VERSION 5.8 ;
BUSBITCHARS "[]" ;
DIVIDERCHAR "/" ;
UNITS
    DATABASE MICRONS 1000 ;
END UNITS

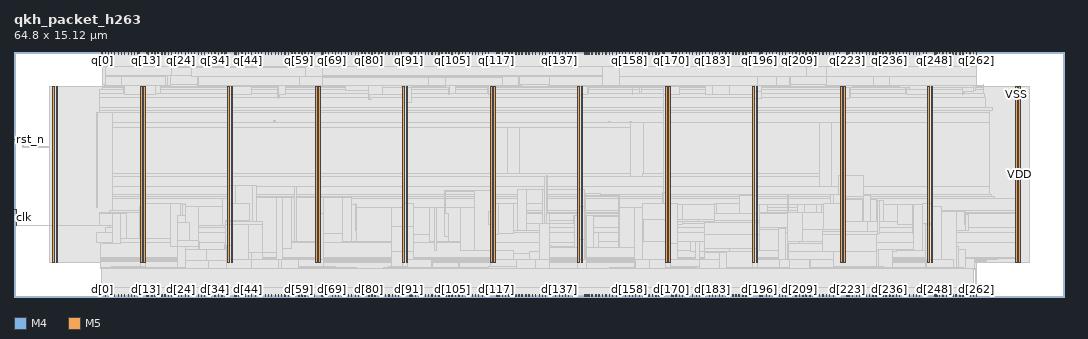
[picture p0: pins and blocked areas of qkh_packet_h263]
MACRO qkh_packet_h263
  FOREIGN qkh_packet_h263 0 0 ;
  CLASS BLOCK ;
  SIZE 64.8 BY 15.12 ;
  PIN clk
    DIRECTION INPUT ;
    USE SIGNAL ;
    PORT
      LAYER M4 ;
        RECT  0.054 5.376 0.138 5.4 ;
    END
    PORT
      LAYER M4 ;
        RECT  0.108 5.376 0.133 5.4 ;
    END
    PORT
      LAYER M4 ;
        RECT  0.133 4.416 0.179 5.4 ;
    END
  END clk
  PIN d[0]
    DIRECTION INPUT ;
    USE SIGNAL ;
    PORT
      LAYER M5 ;
        RECT  5.424 0.054 5.448 0.138 ;
    END
  END d[0]
  PIN d[100]
    DIRECTION INPUT ;
    USE SIGNAL ;
    PORT
      LAYER M5 ;
        RECT  26.016 0.054 26.04 0.138 ;
    END
  END d[100]
  PIN d[101]
    DIRECTION INPUT ;
    USE SIGNAL ;
    PORT
      LAYER M5 ;
        RECT  26.208 0.054 26.232 0.138 ;
    END
  END d[101]
  PIN d[102]
    DIRECTION INPUT ;
    USE SIGNAL ;
    PORT
      LAYER M5 ;
        RECT  26.4 0.054 26.424 0.138 ;
    END
  END d[102]
  PIN d[103]
    DIRECTION INPUT ;
    USE SIGNAL ;
    PORT
      LAYER M5 ;
        RECT  26.64 0.054 26.664 0.138 ;
    END
  END d[103]
  PIN d[104]
    DIRECTION INPUT ;
    USE SIGNAL ;
    PORT
      LAYER M5 ;
        RECT  26.832 0.054 26.856 0.138 ;
    END
  END d[104]
  PIN d[105]
    DIRECTION INPUT ;
    USE SIGNAL ;
    PORT
      LAYER M5 ;
        RECT  27.024 0.054 27.048 0.138 ;
    END
  END d[105]
  PIN d[106]
    DIRECTION INPUT ;
    USE SIGNAL ;
    PORT
      LAYER M5 ;
        RECT  27.216 0.054 27.24 0.138 ;
    END
  END d[106]
  PIN d[107]
    DIRECTION INPUT ;
    USE SIGNAL ;
    PORT
      LAYER M5 ;
        RECT  27.456 0.054 27.48 0.138 ;
    END
  END d[107]
  PIN d[108]
    DIRECTION INPUT ;
    USE SIGNAL ;
    PORT
      LAYER M5 ;
        RECT  27.648 0.054 27.672 0.138 ;
    END
  END d[108]
  PIN d[109]
    DIRECTION INPUT ;
    USE SIGNAL ;
    PORT
      LAYER M5 ;
        RECT  27.84 0.054 27.864 0.138 ;
    END
  END d[109]
  PIN d[10]
    DIRECTION INPUT ;
    USE SIGNAL ;
    PORT
      LAYER M5 ;
        RECT  7.44 0.054 7.464 0.138 ;
    END
  END d[10]
  PIN d[110]
    DIRECTION INPUT ;
    USE SIGNAL ;
    PORT
      LAYER M5 ;
        RECT  28.08 0.054 28.104 0.138 ;
    END
  END d[110]
  PIN d[111]
    DIRECTION INPUT ;
    USE SIGNAL ;
    PORT
      LAYER M5 ;
        RECT  28.272 0.054 28.296 0.138 ;
    END
  END d[111]
  PIN d[112]
    DIRECTION INPUT ;
    USE SIGNAL ;
    PORT
      LAYER M5 ;
        RECT  28.464 0.054 28.488 0.138 ;
    END
  END d[112]
  PIN d[113]
    DIRECTION INPUT ;
    USE SIGNAL ;
    PORT
      LAYER M5 ;
        RECT  28.656 0.054 28.68 0.138 ;
    END
  END d[113]
  PIN d[114]
    DIRECTION INPUT ;
    USE SIGNAL ;
    PORT
      LAYER M5 ;
        RECT  28.896 0.054 28.92 0.138 ;
    END
  END d[114]
  PIN d[115]
    DIRECTION INPUT ;
    USE SIGNAL ;
    PORT
      LAYER M5 ;
        RECT  29.088 0.054 29.112 0.138 ;
    END
  END d[115]
  PIN d[116]
    DIRECTION INPUT ;
    USE SIGNAL ;
    PORT
      LAYER M5 ;
        RECT  29.28 0.054 29.304 0.138 ;
    END
  END d[116]
  PIN d[117]
    DIRECTION INPUT ;
    USE SIGNAL ;
    PORT
      LAYER M5 ;
        RECT  29.76 0.054 29.784 0.138 ;
    END
  END d[117]
  PIN d[118]
    DIRECTION INPUT ;
    USE SIGNAL ;
    PORT
      LAYER M5 ;
        RECT  29.856 0.054 29.88 0.138 ;
    END
  END d[118]
  PIN d[119]
    DIRECTION INPUT ;
    USE SIGNAL ;
    PORT
      LAYER M5 ;
        RECT  29.952 0.054 29.976 0.138 ;
    END
  END d[119]
  PIN d[11]
    DIRECTION INPUT ;
    USE SIGNAL ;
    PORT
      LAYER M5 ;
        RECT  7.632 0.054 7.656 0.138 ;
    END
  END d[11]
  PIN d[120]
    DIRECTION INPUT ;
    USE SIGNAL ;
    PORT
      LAYER M5 ;
        RECT  30.144 0.054 30.168 0.138 ;
    END
  END d[120]
  PIN d[121]
    DIRECTION INPUT ;
    USE SIGNAL ;
    PORT
      LAYER M5 ;
        RECT  30.336 0.054 30.36 0.138 ;
    END
  END d[121]
  PIN d[122]
    DIRECTION INPUT ;
    USE SIGNAL ;
    PORT
      LAYER M5 ;
        RECT  30.528 0.054 30.552 0.138 ;
    END
  END d[122]
  PIN d[123]
    DIRECTION INPUT ;
    USE SIGNAL ;
    PORT
      LAYER M5 ;
        RECT  30.72 0.054 30.744 0.138 ;
    END
  END d[123]
  PIN d[124]
    DIRECTION INPUT ;
    USE SIGNAL ;
    PORT
      LAYER M5 ;
        RECT  30.96 0.054 30.984 0.138 ;
    END
  END d[124]
  PIN d[125]
    DIRECTION INPUT ;
    USE SIGNAL ;
    PORT
      LAYER M5 ;
        RECT  31.152 0.054 31.176 0.138 ;
    END
  END d[125]
  PIN d[126]
    DIRECTION INPUT ;
    USE SIGNAL ;
    PORT
      LAYER M5 ;
        RECT  31.344 0.054 31.368 0.138 ;
    END
  END d[126]
  PIN d[127]
    DIRECTION INPUT ;
    USE SIGNAL ;
    PORT
      LAYER M5 ;
        RECT  31.584 0.054 31.608 0.138 ;
    END
  END d[127]
  PIN d[128]
    DIRECTION INPUT ;
    USE SIGNAL ;
    PORT
      LAYER M5 ;
        RECT  31.776 0.054 31.8 0.138 ;
    END
  END d[128]
  PIN d[129]
    DIRECTION INPUT ;
    USE SIGNAL ;
    PORT
      LAYER M5 ;
        RECT  31.968 0.054 31.992 0.138 ;
    END
  END d[129]
  PIN d[12]
    DIRECTION INPUT ;
    USE SIGNAL ;
    PORT
      LAYER M5 ;
        RECT  7.728 0.054 7.752 0.138 ;
    END
  END d[12]
  PIN d[130]
    DIRECTION INPUT ;
    USE SIGNAL ;
    PORT
      LAYER M5 ;
        RECT  32.16 0.054 32.184 0.138 ;
    END
  END d[130]
  PIN d[131]
    DIRECTION INPUT ;
    USE SIGNAL ;
    PORT
      LAYER M5 ;
        RECT  32.4 0.054 32.424 0.138 ;
    END
  END d[131]
  PIN d[132]
    DIRECTION INPUT ;
    USE SIGNAL ;
    PORT
      LAYER M5 ;
        RECT  32.592 0.054 32.616 0.138 ;
    END
  END d[132]
  PIN d[133]
    DIRECTION INPUT ;
    USE SIGNAL ;
    PORT
      LAYER M5 ;
        RECT  32.784 0.054 32.808 0.138 ;
    END
  END d[133]
  PIN d[134]
    DIRECTION INPUT ;
    USE SIGNAL ;
    PORT
      LAYER M5 ;
        RECT  33.024 0.054 33.048 0.138 ;
    END
  END d[134]
  PIN d[135]
    DIRECTION INPUT ;
    USE SIGNAL ;
    PORT
      LAYER M5 ;
        RECT  33.216 0.054 33.24 0.138 ;
    END
  END d[135]
  PIN d[136]
    DIRECTION INPUT ;
    USE SIGNAL ;
    PORT
      LAYER M5 ;
        RECT  33.408 0.054 33.432 0.138 ;
    END
  END d[136]
  PIN d[137]
    DIRECTION INPUT ;
    USE SIGNAL ;
    PORT
      LAYER M5 ;
        RECT  33.648 0.054 33.672 0.138 ;
    END
  END d[137]
  PIN d[138]
    DIRECTION INPUT ;
    USE SIGNAL ;
    PORT
      LAYER M5 ;
        RECT  33.84 0.054 33.864 0.138 ;
    END
  END d[138]
  PIN d[139]
    DIRECTION INPUT ;
    USE SIGNAL ;
    PORT
      LAYER M5 ;
        RECT  34.032 0.054 34.056 0.138 ;
    END
  END d[139]
  PIN d[13]
    DIRECTION INPUT ;
    USE SIGNAL ;
    PORT
      LAYER M5 ;
        RECT  8.16 0.054 8.184 0.138 ;
    END
  END d[13]
  PIN d[140]
    DIRECTION INPUT ;
    USE SIGNAL ;
    PORT
      LAYER M5 ;
        RECT  34.224 0.054 34.248 0.138 ;
    END
  END d[140]
  PIN d[141]
    DIRECTION INPUT ;
    USE SIGNAL ;
    PORT
      LAYER M5 ;
        RECT  34.464 0.054 34.488 0.138 ;
    END
  END d[141]
  PIN d[142]
    DIRECTION INPUT ;
    USE SIGNAL ;
    PORT
      LAYER M5 ;
        RECT  34.656 0.054 34.68 0.138 ;
    END
  END d[142]
  PIN d[143]
    DIRECTION INPUT ;
    USE SIGNAL ;
    PORT
      LAYER M5 ;
        RECT  35.184 0.054 35.208 0.138 ;
    END
  END d[143]
  PIN d[144]
    DIRECTION INPUT ;
    USE SIGNAL ;
    PORT
      LAYER M5 ;
        RECT  35.28 0.054 35.304 0.138 ;
    END
  END d[144]
  PIN d[145]
    DIRECTION INPUT ;
    USE SIGNAL ;
    PORT
      LAYER M5 ;
        RECT  35.376 0.054 35.4 0.138 ;
    END
  END d[145]
  PIN d[146]
    DIRECTION INPUT ;
    USE SIGNAL ;
    PORT
      LAYER M5 ;
        RECT  35.472 0.054 35.496 0.138 ;
    END
  END d[146]
  PIN d[147]
    DIRECTION INPUT ;
    USE SIGNAL ;
    PORT
      LAYER M5 ;
        RECT  35.664 0.054 35.688 0.138 ;
    END
  END d[147]
  PIN d[148]
    DIRECTION INPUT ;
    USE SIGNAL ;
    PORT
      LAYER M5 ;
        RECT  35.904 0.054 35.928 0.138 ;
    END
  END d[148]
  PIN d[149]
    DIRECTION INPUT ;
    USE SIGNAL ;
    PORT
      LAYER M5 ;
        RECT  36.096 0.054 36.12 0.138 ;
    END
  END d[149]
  PIN d[14]
    DIRECTION INPUT ;
    USE SIGNAL ;
    PORT
      LAYER M5 ;
        RECT  8.256 0.054 8.28 0.138 ;
    END
  END d[14]
  PIN d[150]
    DIRECTION INPUT ;
    USE SIGNAL ;
    PORT
      LAYER M5 ;
        RECT  36.288 0.054 36.312 0.138 ;
    END
  END d[150]
  PIN d[151]
    DIRECTION INPUT ;
    USE SIGNAL ;
    PORT
      LAYER M5 ;
        RECT  36.528 0.054 36.552 0.138 ;
    END
  END d[151]
  PIN d[152]
    DIRECTION INPUT ;
    USE SIGNAL ;
    PORT
      LAYER M5 ;
        RECT  36.72 0.054 36.744 0.138 ;
    END
  END d[152]
  PIN d[153]
    DIRECTION INPUT ;
    USE SIGNAL ;
    PORT
      LAYER M5 ;
        RECT  36.912 0.054 36.936 0.138 ;
    END
  END d[153]
  PIN d[154]
    DIRECTION INPUT ;
    USE SIGNAL ;
    PORT
      LAYER M5 ;
        RECT  37.152 0.054 37.176 0.138 ;
    END
  END d[154]
  PIN d[155]
    DIRECTION INPUT ;
    USE SIGNAL ;
    PORT
      LAYER M5 ;
        RECT  37.344 0.054 37.368 0.138 ;
    END
  END d[155]
  PIN d[156]
    DIRECTION INPUT ;
    USE SIGNAL ;
    PORT
      LAYER M5 ;
        RECT  37.536 0.054 37.56 0.138 ;
    END
  END d[156]
  PIN d[157]
    DIRECTION INPUT ;
    USE SIGNAL ;
    PORT
      LAYER M5 ;
        RECT  37.728 0.054 37.752 0.138 ;
    END
  END d[157]
  PIN d[158]
    DIRECTION INPUT ;
    USE SIGNAL ;
    PORT
      LAYER M5 ;
        RECT  37.968 0.054 37.992 0.138 ;
    END
  END d[158]
  PIN d[159]
    DIRECTION INPUT ;
    USE SIGNAL ;
    PORT
      LAYER M5 ;
        RECT  38.16 0.054 38.184 0.138 ;
    END
  END d[159]
  PIN d[15]
    DIRECTION INPUT ;
    USE SIGNAL ;
    PORT
      LAYER M5 ;
        RECT  8.496 0.054 8.52 0.138 ;
    END
  END d[15]
  PIN d[160]
    DIRECTION INPUT ;
    USE SIGNAL ;
    PORT
      LAYER M5 ;
        RECT  38.352 0.054 38.376 0.138 ;
    END
  END d[160]
  PIN d[161]
    DIRECTION INPUT ;
    USE SIGNAL ;
    PORT
      LAYER M5 ;
        RECT  38.592 0.054 38.616 0.138 ;
    END
  END d[161]
  PIN d[162]
    DIRECTION INPUT ;
    USE SIGNAL ;
    PORT
      LAYER M5 ;
        RECT  38.784 0.054 38.808 0.138 ;
    END
  END d[162]
  PIN d[163]
    DIRECTION INPUT ;
    USE SIGNAL ;
    PORT
      LAYER M5 ;
        RECT  38.976 0.054 39 0.138 ;
    END
  END d[163]
  PIN d[164]
    DIRECTION INPUT ;
    USE SIGNAL ;
    PORT
      LAYER M5 ;
        RECT  39.168 0.054 39.192 0.138 ;
    END
  END d[164]
  PIN d[165]
    DIRECTION INPUT ;
    USE SIGNAL ;
    PORT
      LAYER M5 ;
        RECT  39.408 0.054 39.432 0.138 ;
    END
  END d[165]
  PIN d[166]
    DIRECTION INPUT ;
    USE SIGNAL ;
    PORT
      LAYER M5 ;
        RECT  39.6 0.054 39.624 0.138 ;
    END
  END d[166]
  PIN d[167]
    DIRECTION INPUT ;
    USE SIGNAL ;
    PORT
      LAYER M5 ;
        RECT  39.792 0.054 39.816 0.138 ;
    END
  END d[167]
  PIN d[168]
    DIRECTION INPUT ;
    USE SIGNAL ;
    PORT
      LAYER M5 ;
        RECT  40.032 0.054 40.056 0.138 ;
    END
  END d[168]
  PIN d[169]
    DIRECTION INPUT ;
    USE SIGNAL ;
    PORT
      LAYER M5 ;
        RECT  40.128 0.054 40.152 0.138 ;
    END
  END d[169]
  PIN d[16]
    DIRECTION INPUT ;
    USE SIGNAL ;
    PORT
      LAYER M5 ;
        RECT  8.688 0.054 8.712 0.138 ;
    END
  END d[16]
  PIN d[170]
    DIRECTION INPUT ;
    USE SIGNAL ;
    PORT
      LAYER M5 ;
        RECT  40.56 0.054 40.584 0.138 ;
    END
  END d[170]
  PIN d[171]
    DIRECTION INPUT ;
    USE SIGNAL ;
    PORT
      LAYER M5 ;
        RECT  40.656 0.054 40.68 0.138 ;
    END
  END d[171]
  PIN d[172]
    DIRECTION INPUT ;
    USE SIGNAL ;
    PORT
      LAYER M5 ;
        RECT  40.848 0.054 40.872 0.138 ;
    END
  END d[172]
  PIN d[173]
    DIRECTION INPUT ;
    USE SIGNAL ;
    PORT
      LAYER M5 ;
        RECT  41.04 0.054 41.064 0.138 ;
    END
  END d[173]
  PIN d[174]
    DIRECTION INPUT ;
    USE SIGNAL ;
    PORT
      LAYER M5 ;
        RECT  41.232 0.054 41.256 0.138 ;
    END
  END d[174]
  PIN d[175]
    DIRECTION INPUT ;
    USE SIGNAL ;
    PORT
      LAYER M5 ;
        RECT  41.472 0.054 41.496 0.138 ;
    END
  END d[175]
  PIN d[176]
    DIRECTION INPUT ;
    USE SIGNAL ;
    PORT
      LAYER M5 ;
        RECT  41.664 0.054 41.688 0.138 ;
    END
  END d[176]
  PIN d[177]
    DIRECTION INPUT ;
    USE SIGNAL ;
    PORT
      LAYER M5 ;
        RECT  41.856 0.054 41.88 0.138 ;
    END
  END d[177]
  PIN d[178]
    DIRECTION INPUT ;
    USE SIGNAL ;
    PORT
      LAYER M5 ;
        RECT  42.096 0.054 42.12 0.138 ;
    END
  END d[178]
  PIN d[179]
    DIRECTION INPUT ;
    USE SIGNAL ;
    PORT
      LAYER M5 ;
        RECT  42.288 0.054 42.312 0.138 ;
    END
  END d[179]
  PIN d[17]
    DIRECTION INPUT ;
    USE SIGNAL ;
    PORT
      LAYER M5 ;
        RECT  8.88 0.054 8.904 0.138 ;
    END
  END d[17]
  PIN d[180]
    DIRECTION INPUT ;
    USE SIGNAL ;
    PORT
      LAYER M5 ;
        RECT  42.48 0.054 42.504 0.138 ;
    END
  END d[180]
  PIN d[181]
    DIRECTION INPUT ;
    USE SIGNAL ;
    PORT
      LAYER M5 ;
        RECT  42.672 0.054 42.696 0.138 ;
    END
  END d[181]
  PIN d[182]
    DIRECTION INPUT ;
    USE SIGNAL ;
    PORT
      LAYER M5 ;
        RECT  42.912 0.054 42.936 0.138 ;
    END
  END d[182]
  PIN d[183]
    DIRECTION INPUT ;
    USE SIGNAL ;
    PORT
      LAYER M5 ;
        RECT  43.104 0.054 43.128 0.138 ;
    END
  END d[183]
  PIN d[184]
    DIRECTION INPUT ;
    USE SIGNAL ;
    PORT
      LAYER M5 ;
        RECT  43.296 0.054 43.32 0.138 ;
    END
  END d[184]
  PIN d[185]
    DIRECTION INPUT ;
    USE SIGNAL ;
    PORT
      LAYER M5 ;
        RECT  43.536 0.054 43.56 0.138 ;
    END
  END d[185]
  PIN d[186]
    DIRECTION INPUT ;
    USE SIGNAL ;
    PORT
      LAYER M5 ;
        RECT  43.728 0.054 43.752 0.138 ;
    END
  END d[186]
  PIN d[187]
    DIRECTION INPUT ;
    USE SIGNAL ;
    PORT
      LAYER M5 ;
        RECT  43.92 0.054 43.944 0.138 ;
    END
  END d[187]
  PIN d[188]
    DIRECTION INPUT ;
    USE SIGNAL ;
    PORT
      LAYER M5 ;
        RECT  44.16 0.054 44.184 0.138 ;
    END
  END d[188]
  PIN d[189]
    DIRECTION INPUT ;
    USE SIGNAL ;
    PORT
      LAYER M5 ;
        RECT  44.352 0.054 44.376 0.138 ;
    END
  END d[189]
  PIN d[18]
    DIRECTION INPUT ;
    USE SIGNAL ;
    PORT
      LAYER M5 ;
        RECT  9.12 0.054 9.144 0.138 ;
    END
  END d[18]
  PIN d[190]
    DIRECTION INPUT ;
    USE SIGNAL ;
    PORT
      LAYER M5 ;
        RECT  44.544 0.054 44.568 0.138 ;
    END
  END d[190]
  PIN d[191]
    DIRECTION INPUT ;
    USE SIGNAL ;
    PORT
      LAYER M5 ;
        RECT  44.736 0.054 44.76 0.138 ;
    END
  END d[191]
  PIN d[192]
    DIRECTION INPUT ;
    USE SIGNAL ;
    PORT
      LAYER M5 ;
        RECT  44.976 0.054 45 0.138 ;
    END
  END d[192]
  PIN d[193]
    DIRECTION INPUT ;
    USE SIGNAL ;
    PORT
      LAYER M5 ;
        RECT  45.168 0.054 45.192 0.138 ;
    END
  END d[193]
  PIN d[194]
    DIRECTION INPUT ;
    USE SIGNAL ;
    PORT
      LAYER M5 ;
        RECT  45.36 0.054 45.384 0.138 ;
    END
  END d[194]
  PIN d[195]
    DIRECTION INPUT ;
    USE SIGNAL ;
    PORT
      LAYER M5 ;
        RECT  45.504 0.054 45.528 0.138 ;
    END
  END d[195]
  PIN d[196]
    DIRECTION INPUT ;
    USE SIGNAL ;
    PORT
      LAYER M5 ;
        RECT  45.984 0.054 46.008 0.138 ;
    END
  END d[196]
  PIN d[197]
    DIRECTION INPUT ;
    USE SIGNAL ;
    PORT
      LAYER M5 ;
        RECT  46.08 0.054 46.104 0.138 ;
    END
  END d[197]
  PIN d[198]
    DIRECTION INPUT ;
    USE SIGNAL ;
    PORT
      LAYER M5 ;
        RECT  46.176 0.054 46.2 0.138 ;
    END
  END d[198]
  PIN d[199]
    DIRECTION INPUT ;
    USE SIGNAL ;
    PORT
      LAYER M5 ;
        RECT  46.416 0.054 46.44 0.138 ;
    END
  END d[199]
  PIN d[19]
    DIRECTION INPUT ;
    USE SIGNAL ;
    PORT
      LAYER M5 ;
        RECT  9.312 0.054 9.336 0.138 ;
    END
  END d[19]
  PIN d[1]
    DIRECTION INPUT ;
    USE SIGNAL ;
    PORT
      LAYER M5 ;
        RECT  5.616 0.054 5.64 0.138 ;
    END
  END d[1]
  PIN d[200]
    DIRECTION INPUT ;
    USE SIGNAL ;
    PORT
      LAYER M5 ;
        RECT  46.608 0.054 46.632 0.138 ;
    END
  END d[200]
  PIN d[201]
    DIRECTION INPUT ;
    USE SIGNAL ;
    PORT
      LAYER M5 ;
        RECT  46.8 0.054 46.824 0.138 ;
    END
  END d[201]
  PIN d[202]
    DIRECTION INPUT ;
    USE SIGNAL ;
    PORT
      LAYER M5 ;
        RECT  47.04 0.054 47.064 0.138 ;
    END
  END d[202]
  PIN d[203]
    DIRECTION INPUT ;
    USE SIGNAL ;
    PORT
      LAYER M5 ;
        RECT  47.232 0.054 47.256 0.138 ;
    END
  END d[203]
  PIN d[204]
    DIRECTION INPUT ;
    USE SIGNAL ;
    PORT
      LAYER M5 ;
        RECT  47.424 0.054 47.448 0.138 ;
    END
  END d[204]
  PIN d[205]
    DIRECTION INPUT ;
    USE SIGNAL ;
    PORT
      LAYER M5 ;
        RECT  47.616 0.054 47.64 0.138 ;
    END
  END d[205]
  PIN d[206]
    DIRECTION INPUT ;
    USE SIGNAL ;
    PORT
      LAYER M5 ;
        RECT  47.856 0.054 47.88 0.138 ;
    END
  END d[206]
  PIN d[207]
    DIRECTION INPUT ;
    USE SIGNAL ;
    PORT
      LAYER M5 ;
        RECT  48.048 0.054 48.072 0.138 ;
    END
  END d[207]
  PIN d[208]
    DIRECTION INPUT ;
    USE SIGNAL ;
    PORT
      LAYER M5 ;
        RECT  48.24 0.054 48.264 0.138 ;
    END
  END d[208]
  PIN d[209]
    DIRECTION INPUT ;
    USE SIGNAL ;
    PORT
      LAYER M5 ;
        RECT  48.48 0.054 48.504 0.138 ;
    END
  END d[209]
  PIN d[20]
    DIRECTION INPUT ;
    USE SIGNAL ;
    PORT
      LAYER M5 ;
        RECT  9.504 0.054 9.528 0.138 ;
    END
  END d[20]
  PIN d[210]
    DIRECTION INPUT ;
    USE SIGNAL ;
    PORT
      LAYER M5 ;
        RECT  48.672 0.054 48.696 0.138 ;
    END
  END d[210]
  PIN d[211]
    DIRECTION INPUT ;
    USE SIGNAL ;
    PORT
      LAYER M5 ;
        RECT  48.864 0.054 48.888 0.138 ;
    END
  END d[211]
  PIN d[212]
    DIRECTION INPUT ;
    USE SIGNAL ;
    PORT
      LAYER M5 ;
        RECT  49.104 0.054 49.128 0.138 ;
    END
  END d[212]
  PIN d[213]
    DIRECTION INPUT ;
    USE SIGNAL ;
    PORT
      LAYER M5 ;
        RECT  49.296 0.054 49.32 0.138 ;
    END
  END d[213]
  PIN d[214]
    DIRECTION INPUT ;
    USE SIGNAL ;
    PORT
      LAYER M5 ;
        RECT  49.488 0.054 49.512 0.138 ;
    END
  END d[214]
  PIN d[215]
    DIRECTION INPUT ;
    USE SIGNAL ;
    PORT
      LAYER M5 ;
        RECT  49.68 0.054 49.704 0.138 ;
    END
  END d[215]
  PIN d[216]
    DIRECTION INPUT ;
    USE SIGNAL ;
    PORT
      LAYER M5 ;
        RECT  49.92 0.054 49.944 0.138 ;
    END
  END d[216]
  PIN d[217]
    DIRECTION INPUT ;
    USE SIGNAL ;
    PORT
      LAYER M5 ;
        RECT  50.112 0.054 50.136 0.138 ;
    END
  END d[217]
  PIN d[218]
    DIRECTION INPUT ;
    USE SIGNAL ;
    PORT
      LAYER M5 ;
        RECT  50.304 0.054 50.328 0.138 ;
    END
  END d[218]
  PIN d[219]
    DIRECTION INPUT ;
    USE SIGNAL ;
    PORT
      LAYER M5 ;
        RECT  50.544 0.054 50.568 0.138 ;
    END
  END d[219]
  PIN d[21]
    DIRECTION INPUT ;
    USE SIGNAL ;
    PORT
      LAYER M5 ;
        RECT  9.696 0.054 9.72 0.138 ;
    END
  END d[21]
  PIN d[220]
    DIRECTION INPUT ;
    USE SIGNAL ;
    PORT
      LAYER M5 ;
        RECT  50.736 0.054 50.76 0.138 ;
    END
  END d[220]
  PIN d[221]
    DIRECTION INPUT ;
    USE SIGNAL ;
    PORT
      LAYER M5 ;
        RECT  50.928 0.054 50.952 0.138 ;
    END
  END d[221]
  PIN d[222]
    DIRECTION INPUT ;
    USE SIGNAL ;
    PORT
      LAYER M5 ;
        RECT  51.36 0.054 51.384 0.138 ;
    END
  END d[222]
  PIN d[223]
    DIRECTION INPUT ;
    USE SIGNAL ;
    PORT
      LAYER M5 ;
        RECT  51.456 0.054 51.48 0.138 ;
    END
  END d[223]
  PIN d[224]
    DIRECTION INPUT ;
    USE SIGNAL ;
    PORT
      LAYER M5 ;
        RECT  51.552 0.054 51.576 0.138 ;
    END
  END d[224]
  PIN d[225]
    DIRECTION INPUT ;
    USE SIGNAL ;
    PORT
      LAYER M5 ;
        RECT  51.744 0.054 51.768 0.138 ;
    END
  END d[225]
  PIN d[226]
    DIRECTION INPUT ;
    USE SIGNAL ;
    PORT
      LAYER M5 ;
        RECT  51.984 0.054 52.008 0.138 ;
    END
  END d[226]
  PIN d[227]
    DIRECTION INPUT ;
    USE SIGNAL ;
    PORT
      LAYER M5 ;
        RECT  52.176 0.054 52.2 0.138 ;
    END
  END d[227]
  PIN d[228]
    DIRECTION INPUT ;
    USE SIGNAL ;
    PORT
      LAYER M5 ;
        RECT  52.368 0.054 52.392 0.138 ;
    END
  END d[228]
  PIN d[229]
    DIRECTION INPUT ;
    USE SIGNAL ;
    PORT
      LAYER M5 ;
        RECT  52.608 0.054 52.632 0.138 ;
    END
  END d[229]
  PIN d[22]
    DIRECTION INPUT ;
    USE SIGNAL ;
    PORT
      LAYER M5 ;
        RECT  9.936 0.054 9.96 0.138 ;
    END
  END d[22]
  PIN d[230]
    DIRECTION INPUT ;
    USE SIGNAL ;
    PORT
      LAYER M5 ;
        RECT  52.8 0.054 52.824 0.138 ;
    END
  END d[230]
  PIN d[231]
    DIRECTION INPUT ;
    USE SIGNAL ;
    PORT
      LAYER M5 ;
        RECT  52.992 0.054 53.016 0.138 ;
    END
  END d[231]
  PIN d[232]
    DIRECTION INPUT ;
    USE SIGNAL ;
    PORT
      LAYER M5 ;
        RECT  53.184 0.054 53.208 0.138 ;
    END
  END d[232]
  PIN d[233]
    DIRECTION INPUT ;
    USE SIGNAL ;
    PORT
      LAYER M5 ;
        RECT  53.424 0.054 53.448 0.138 ;
    END
  END d[233]
  PIN d[234]
    DIRECTION INPUT ;
    USE SIGNAL ;
    PORT
      LAYER M5 ;
        RECT  53.616 0.054 53.64 0.138 ;
    END
  END d[234]
  PIN d[235]
    DIRECTION INPUT ;
    USE SIGNAL ;
    PORT
      LAYER M5 ;
        RECT  53.808 0.054 53.832 0.138 ;
    END
  END d[235]
  PIN d[236]
    DIRECTION INPUT ;
    USE SIGNAL ;
    PORT
      LAYER M5 ;
        RECT  54.048 0.054 54.072 0.138 ;
    END
  END d[236]
  PIN d[237]
    DIRECTION INPUT ;
    USE SIGNAL ;
    PORT
      LAYER M5 ;
        RECT  54.24 0.054 54.264 0.138 ;
    END
  END d[237]
  PIN d[238]
    DIRECTION INPUT ;
    USE SIGNAL ;
    PORT
      LAYER M5 ;
        RECT  54.432 0.054 54.456 0.138 ;
    END
  END d[238]
  PIN d[239]
    DIRECTION INPUT ;
    USE SIGNAL ;
    PORT
      LAYER M5 ;
        RECT  54.624 0.054 54.648 0.138 ;
    END
  END d[239]
  PIN d[23]
    DIRECTION INPUT ;
    USE SIGNAL ;
    PORT
      LAYER M5 ;
        RECT  10.128 0.054 10.152 0.138 ;
    END
  END d[23]
  PIN d[240]
    DIRECTION INPUT ;
    USE SIGNAL ;
    PORT
      LAYER M5 ;
        RECT  54.864 0.054 54.888 0.138 ;
    END
  END d[240]
  PIN d[241]
    DIRECTION INPUT ;
    USE SIGNAL ;
    PORT
      LAYER M5 ;
        RECT  55.056 0.054 55.08 0.138 ;
    END
  END d[241]
  PIN d[242]
    DIRECTION INPUT ;
    USE SIGNAL ;
    PORT
      LAYER M5 ;
        RECT  55.248 0.054 55.272 0.138 ;
    END
  END d[242]
  PIN d[243]
    DIRECTION INPUT ;
    USE SIGNAL ;
    PORT
      LAYER M5 ;
        RECT  55.488 0.054 55.512 0.138 ;
    END
  END d[243]
  PIN d[244]
    DIRECTION INPUT ;
    USE SIGNAL ;
    PORT
      LAYER M5 ;
        RECT  55.68 0.054 55.704 0.138 ;
    END
  END d[244]
  PIN d[245]
    DIRECTION INPUT ;
    USE SIGNAL ;
    PORT
      LAYER M5 ;
        RECT  55.872 0.054 55.896 0.138 ;
    END
  END d[245]
  PIN d[246]
    DIRECTION INPUT ;
    USE SIGNAL ;
    PORT
      LAYER M5 ;
        RECT  56.112 0.054 56.136 0.138 ;
    END
  END d[246]
  PIN d[247]
    DIRECTION INPUT ;
    USE SIGNAL ;
    PORT
      LAYER M5 ;
        RECT  56.304 0.054 56.328 0.138 ;
    END
  END d[247]
  PIN d[248]
    DIRECTION INPUT ;
    USE SIGNAL ;
    PORT
      LAYER M5 ;
        RECT  56.784 0.054 56.808 0.138 ;
    END
  END d[248]
  PIN d[249]
    DIRECTION INPUT ;
    USE SIGNAL ;
    PORT
      LAYER M5 ;
        RECT  56.88 0.054 56.904 0.138 ;
    END
  END d[249]
  PIN d[24]
    DIRECTION INPUT ;
    USE SIGNAL ;
    PORT
      LAYER M5 ;
        RECT  10.32 0.054 10.344 0.138 ;
    END
  END d[24]
  PIN d[250]
    DIRECTION INPUT ;
    USE SIGNAL ;
    PORT
      LAYER M5 ;
        RECT  56.976 0.054 57 0.138 ;
    END
  END d[250]
  PIN d[251]
    DIRECTION INPUT ;
    USE SIGNAL ;
    PORT
      LAYER M5 ;
        RECT  57.12 0.054 57.144 0.138 ;
    END
  END d[251]
  PIN d[252]
    DIRECTION INPUT ;
    USE SIGNAL ;
    PORT
      LAYER M5 ;
        RECT  57.312 0.054 57.336 0.138 ;
    END
  END d[252]
  PIN d[253]
    DIRECTION INPUT ;
    USE SIGNAL ;
    PORT
      LAYER M5 ;
        RECT  57.552 0.054 57.576 0.138 ;
    END
  END d[253]
  PIN d[254]
    DIRECTION INPUT ;
    USE SIGNAL ;
    PORT
      LAYER M5 ;
        RECT  57.744 0.054 57.768 0.138 ;
    END
  END d[254]
  PIN d[255]
    DIRECTION INPUT ;
    USE SIGNAL ;
    PORT
      LAYER M5 ;
        RECT  57.936 0.054 57.96 0.138 ;
    END
  END d[255]
  PIN d[256]
    DIRECTION INPUT ;
    USE SIGNAL ;
    PORT
      LAYER M5 ;
        RECT  58.128 0.054 58.152 0.138 ;
    END
  END d[256]
  PIN d[257]
    DIRECTION INPUT ;
    USE SIGNAL ;
    PORT
      LAYER M5 ;
        RECT  58.368 0.054 58.392 0.138 ;
    END
  END d[257]
  PIN d[258]
    DIRECTION INPUT ;
    USE SIGNAL ;
    PORT
      LAYER M5 ;
        RECT  58.56 0.054 58.584 0.138 ;
    END
  END d[258]
  PIN d[259]
    DIRECTION INPUT ;
    USE SIGNAL ;
    PORT
      LAYER M5 ;
        RECT  58.752 0.054 58.776 0.138 ;
    END
  END d[259]
  PIN d[25]
    DIRECTION INPUT ;
    USE SIGNAL ;
    PORT
      LAYER M5 ;
        RECT  10.56 0.054 10.584 0.138 ;
    END
  END d[25]
  PIN d[260]
    DIRECTION INPUT ;
    USE SIGNAL ;
    PORT
      LAYER M5 ;
        RECT  58.992 0.054 59.016 0.138 ;
    END
  END d[260]
  PIN d[261]
    DIRECTION INPUT ;
    USE SIGNAL ;
    PORT
      LAYER M5 ;
        RECT  59.184 0.054 59.208 0.138 ;
    END
  END d[261]
  PIN d[262]
    DIRECTION INPUT ;
    USE SIGNAL ;
    PORT
      LAYER M5 ;
        RECT  59.376 0.054 59.4 0.138 ;
    END
  END d[262]
  PIN d[26]
    DIRECTION INPUT ;
    USE SIGNAL ;
    PORT
      LAYER M5 ;
        RECT  10.752 0.054 10.776 0.138 ;
    END
  END d[26]
  PIN d[27]
    DIRECTION INPUT ;
    USE SIGNAL ;
    PORT
      LAYER M5 ;
        RECT  10.944 0.054 10.968 0.138 ;
    END
  END d[27]
  PIN d[28]
    DIRECTION INPUT ;
    USE SIGNAL ;
    PORT
      LAYER M5 ;
        RECT  11.136 0.054 11.16 0.138 ;
    END
  END d[28]
  PIN d[29]
    DIRECTION INPUT ;
    USE SIGNAL ;
    PORT
      LAYER M5 ;
        RECT  11.376 0.054 11.4 0.138 ;
    END
  END d[29]
  PIN d[2]
    DIRECTION INPUT ;
    USE SIGNAL ;
    PORT
      LAYER M5 ;
        RECT  5.808 0.054 5.832 0.138 ;
    END
  END d[2]
  PIN d[30]
    DIRECTION INPUT ;
    USE SIGNAL ;
    PORT
      LAYER M5 ;
        RECT  11.568 0.054 11.592 0.138 ;
    END
  END d[30]
  PIN d[31]
    DIRECTION INPUT ;
    USE SIGNAL ;
    PORT
      LAYER M5 ;
        RECT  11.76 0.054 11.784 0.138 ;
    END
  END d[31]
  PIN d[32]
    DIRECTION INPUT ;
    USE SIGNAL ;
    PORT
      LAYER M5 ;
        RECT  12 0.054 12.024 0.138 ;
    END
  END d[32]
  PIN d[33]
    DIRECTION INPUT ;
    USE SIGNAL ;
    PORT
      LAYER M5 ;
        RECT  12.192 0.054 12.216 0.138 ;
    END
  END d[33]
  PIN d[34]
    DIRECTION INPUT ;
    USE SIGNAL ;
    PORT
      LAYER M5 ;
        RECT  12.384 0.054 12.408 0.138 ;
    END
  END d[34]
  PIN d[35]
    DIRECTION INPUT ;
    USE SIGNAL ;
    PORT
      LAYER M5 ;
        RECT  12.624 0.054 12.648 0.138 ;
    END
  END d[35]
  PIN d[36]
    DIRECTION INPUT ;
    USE SIGNAL ;
    PORT
      LAYER M5 ;
        RECT  12.816 0.054 12.84 0.138 ;
    END
  END d[36]
  PIN d[37]
    DIRECTION INPUT ;
    USE SIGNAL ;
    PORT
      LAYER M5 ;
        RECT  13.008 0.054 13.032 0.138 ;
    END
  END d[37]
  PIN d[38]
    DIRECTION INPUT ;
    USE SIGNAL ;
    PORT
      LAYER M5 ;
        RECT  13.104 0.054 13.128 0.138 ;
    END
  END d[38]
  PIN d[39]
    DIRECTION INPUT ;
    USE SIGNAL ;
    PORT
      LAYER M5 ;
        RECT  13.584 0.054 13.608 0.138 ;
    END
  END d[39]
  PIN d[3]
    DIRECTION INPUT ;
    USE SIGNAL ;
    PORT
      LAYER M5 ;
        RECT  6 0.054 6.024 0.138 ;
    END
  END d[3]
  PIN d[40]
    DIRECTION INPUT ;
    USE SIGNAL ;
    PORT
      LAYER M5 ;
        RECT  13.68 0.054 13.704 0.138 ;
    END
  END d[40]
  PIN d[41]
    DIRECTION INPUT ;
    USE SIGNAL ;
    PORT
      LAYER M5 ;
        RECT  13.824 0.054 13.848 0.138 ;
    END
  END d[41]
  PIN d[42]
    DIRECTION INPUT ;
    USE SIGNAL ;
    PORT
      LAYER M5 ;
        RECT  14.064 0.054 14.088 0.138 ;
    END
  END d[42]
  PIN d[43]
    DIRECTION INPUT ;
    USE SIGNAL ;
    PORT
      LAYER M5 ;
        RECT  14.256 0.054 14.28 0.138 ;
    END
  END d[43]
  PIN d[44]
    DIRECTION INPUT ;
    USE SIGNAL ;
    PORT
      LAYER M5 ;
        RECT  14.448 0.054 14.472 0.138 ;
    END
  END d[44]
  PIN d[45]
    DIRECTION INPUT ;
    USE SIGNAL ;
    PORT
      LAYER M5 ;
        RECT  14.64 0.054 14.664 0.138 ;
    END
  END d[45]
  PIN d[46]
    DIRECTION INPUT ;
    USE SIGNAL ;
    PORT
      LAYER M5 ;
        RECT  14.88 0.054 14.904 0.138 ;
    END
  END d[46]
  PIN d[47]
    DIRECTION INPUT ;
    USE SIGNAL ;
    PORT
      LAYER M5 ;
        RECT  15.072 0.054 15.096 0.138 ;
    END
  END d[47]
  PIN d[48]
    DIRECTION INPUT ;
    USE SIGNAL ;
    PORT
      LAYER M5 ;
        RECT  15.264 0.054 15.288 0.138 ;
    END
  END d[48]
  PIN d[49]
    DIRECTION INPUT ;
    USE SIGNAL ;
    PORT
      LAYER M5 ;
        RECT  15.504 0.054 15.528 0.138 ;
    END
  END d[49]
  PIN d[4]
    DIRECTION INPUT ;
    USE SIGNAL ;
    PORT
      LAYER M5 ;
        RECT  6.192 0.054 6.216 0.138 ;
    END
  END d[4]
  PIN d[50]
    DIRECTION INPUT ;
    USE SIGNAL ;
    PORT
      LAYER M5 ;
        RECT  15.696 0.054 15.72 0.138 ;
    END
  END d[50]
  PIN d[51]
    DIRECTION INPUT ;
    USE SIGNAL ;
    PORT
      LAYER M5 ;
        RECT  15.888 0.054 15.912 0.138 ;
    END
  END d[51]
  PIN d[52]
    DIRECTION INPUT ;
    USE SIGNAL ;
    PORT
      LAYER M5 ;
        RECT  16.128 0.054 16.152 0.138 ;
    END
  END d[52]
  PIN d[53]
    DIRECTION INPUT ;
    USE SIGNAL ;
    PORT
      LAYER M5 ;
        RECT  16.32 0.054 16.344 0.138 ;
    END
  END d[53]
  PIN d[54]
    DIRECTION INPUT ;
    USE SIGNAL ;
    PORT
      LAYER M5 ;
        RECT  16.512 0.054 16.536 0.138 ;
    END
  END d[54]
  PIN d[55]
    DIRECTION INPUT ;
    USE SIGNAL ;
    PORT
      LAYER M5 ;
        RECT  16.704 0.054 16.728 0.138 ;
    END
  END d[55]
  PIN d[56]
    DIRECTION INPUT ;
    USE SIGNAL ;
    PORT
      LAYER M5 ;
        RECT  16.944 0.054 16.968 0.138 ;
    END
  END d[56]
  PIN d[57]
    DIRECTION INPUT ;
    USE SIGNAL ;
    PORT
      LAYER M5 ;
        RECT  17.136 0.054 17.16 0.138 ;
    END
  END d[57]
  PIN d[58]
    DIRECTION INPUT ;
    USE SIGNAL ;
    PORT
      LAYER M5 ;
        RECT  17.328 0.054 17.352 0.138 ;
    END
  END d[58]
  PIN d[59]
    DIRECTION INPUT ;
    USE SIGNAL ;
    PORT
      LAYER M5 ;
        RECT  17.568 0.054 17.592 0.138 ;
    END
  END d[59]
  PIN d[5]
    DIRECTION INPUT ;
    USE SIGNAL ;
    PORT
      LAYER M5 ;
        RECT  6.432 0.054 6.456 0.138 ;
    END
  END d[5]
  PIN d[60]
    DIRECTION INPUT ;
    USE SIGNAL ;
    PORT
      LAYER M5 ;
        RECT  17.76 0.054 17.784 0.138 ;
    END
  END d[60]
  PIN d[61]
    DIRECTION INPUT ;
    USE SIGNAL ;
    PORT
      LAYER M5 ;
        RECT  17.952 0.054 17.976 0.138 ;
    END
  END d[61]
  PIN d[62]
    DIRECTION INPUT ;
    USE SIGNAL ;
    PORT
      LAYER M5 ;
        RECT  18.144 0.054 18.168 0.138 ;
    END
  END d[62]
  PIN d[63]
    DIRECTION INPUT ;
    USE SIGNAL ;
    PORT
      LAYER M5 ;
        RECT  18.384 0.054 18.408 0.138 ;
    END
  END d[63]
  PIN d[64]
    DIRECTION INPUT ;
    USE SIGNAL ;
    PORT
      LAYER M5 ;
        RECT  18.528 0.054 18.552 0.138 ;
    END
  END d[64]
  PIN d[65]
    DIRECTION INPUT ;
    USE SIGNAL ;
    PORT
      LAYER M5 ;
        RECT  18.96 0.054 18.984 0.138 ;
    END
  END d[65]
  PIN d[66]
    DIRECTION INPUT ;
    USE SIGNAL ;
    PORT
      LAYER M5 ;
        RECT  19.056 0.054 19.08 0.138 ;
    END
  END d[66]
  PIN d[67]
    DIRECTION INPUT ;
    USE SIGNAL ;
    PORT
      LAYER M5 ;
        RECT  19.2 0.054 19.224 0.138 ;
    END
  END d[67]
  PIN d[68]
    DIRECTION INPUT ;
    USE SIGNAL ;
    PORT
      LAYER M5 ;
        RECT  19.392 0.054 19.416 0.138 ;
    END
  END d[68]
  PIN d[69]
    DIRECTION INPUT ;
    USE SIGNAL ;
    PORT
      LAYER M5 ;
        RECT  19.632 0.054 19.656 0.138 ;
    END
  END d[69]
  PIN d[6]
    DIRECTION INPUT ;
    USE SIGNAL ;
    PORT
      LAYER M5 ;
        RECT  6.624 0.054 6.648 0.138 ;
    END
  END d[6]
  PIN d[70]
    DIRECTION INPUT ;
    USE SIGNAL ;
    PORT
      LAYER M5 ;
        RECT  19.824 0.054 19.848 0.138 ;
    END
  END d[70]
  PIN d[71]
    DIRECTION INPUT ;
    USE SIGNAL ;
    PORT
      LAYER M5 ;
        RECT  20.016 0.054 20.04 0.138 ;
    END
  END d[71]
  PIN d[72]
    DIRECTION INPUT ;
    USE SIGNAL ;
    PORT
      LAYER M5 ;
        RECT  20.208 0.054 20.232 0.138 ;
    END
  END d[72]
  PIN d[73]
    DIRECTION INPUT ;
    USE SIGNAL ;
    PORT
      LAYER M5 ;
        RECT  20.448 0.054 20.472 0.138 ;
    END
  END d[73]
  PIN d[74]
    DIRECTION INPUT ;
    USE SIGNAL ;
    PORT
      LAYER M5 ;
        RECT  20.64 0.054 20.664 0.138 ;
    END
  END d[74]
  PIN d[75]
    DIRECTION INPUT ;
    USE SIGNAL ;
    PORT
      LAYER M5 ;
        RECT  20.832 0.054 20.856 0.138 ;
    END
  END d[75]
  PIN d[76]
    DIRECTION INPUT ;
    USE SIGNAL ;
    PORT
      LAYER M5 ;
        RECT  21.072 0.054 21.096 0.138 ;
    END
  END d[76]
  PIN d[77]
    DIRECTION INPUT ;
    USE SIGNAL ;
    PORT
      LAYER M5 ;
        RECT  21.264 0.054 21.288 0.138 ;
    END
  END d[77]
  PIN d[78]
    DIRECTION INPUT ;
    USE SIGNAL ;
    PORT
      LAYER M5 ;
        RECT  21.456 0.054 21.48 0.138 ;
    END
  END d[78]
  PIN d[79]
    DIRECTION INPUT ;
    USE SIGNAL ;
    PORT
      LAYER M5 ;
        RECT  21.648 0.054 21.672 0.138 ;
    END
  END d[79]
  PIN d[7]
    DIRECTION INPUT ;
    USE SIGNAL ;
    PORT
      LAYER M5 ;
        RECT  6.816 0.054 6.84 0.138 ;
    END
  END d[7]
  PIN d[80]
    DIRECTION INPUT ;
    USE SIGNAL ;
    PORT
      LAYER M5 ;
        RECT  21.888 0.054 21.912 0.138 ;
    END
  END d[80]
  PIN d[81]
    DIRECTION INPUT ;
    USE SIGNAL ;
    PORT
      LAYER M5 ;
        RECT  22.08 0.054 22.104 0.138 ;
    END
  END d[81]
  PIN d[82]
    DIRECTION INPUT ;
    USE SIGNAL ;
    PORT
      LAYER M5 ;
        RECT  22.272 0.054 22.296 0.138 ;
    END
  END d[82]
  PIN d[83]
    DIRECTION INPUT ;
    USE SIGNAL ;
    PORT
      LAYER M5 ;
        RECT  22.512 0.054 22.536 0.138 ;
    END
  END d[83]
  PIN d[84]
    DIRECTION INPUT ;
    USE SIGNAL ;
    PORT
      LAYER M5 ;
        RECT  22.704 0.054 22.728 0.138 ;
    END
  END d[84]
  PIN d[85]
    DIRECTION INPUT ;
    USE SIGNAL ;
    PORT
      LAYER M5 ;
        RECT  22.896 0.054 22.92 0.138 ;
    END
  END d[85]
  PIN d[86]
    DIRECTION INPUT ;
    USE SIGNAL ;
    PORT
      LAYER M5 ;
        RECT  23.136 0.054 23.16 0.138 ;
    END
  END d[86]
  PIN d[87]
    DIRECTION INPUT ;
    USE SIGNAL ;
    PORT
      LAYER M5 ;
        RECT  23.328 0.054 23.352 0.138 ;
    END
  END d[87]
  PIN d[88]
    DIRECTION INPUT ;
    USE SIGNAL ;
    PORT
      LAYER M5 ;
        RECT  23.52 0.054 23.544 0.138 ;
    END
  END d[88]
  PIN d[89]
    DIRECTION INPUT ;
    USE SIGNAL ;
    PORT
      LAYER M5 ;
        RECT  23.712 0.054 23.736 0.138 ;
    END
  END d[89]
  PIN d[8]
    DIRECTION INPUT ;
    USE SIGNAL ;
    PORT
      LAYER M5 ;
        RECT  7.056 0.054 7.08 0.138 ;
    END
  END d[8]
  PIN d[90]
    DIRECTION INPUT ;
    USE SIGNAL ;
    PORT
      LAYER M5 ;
        RECT  23.904 0.054 23.928 0.138 ;
    END
  END d[90]
  PIN d[91]
    DIRECTION INPUT ;
    USE SIGNAL ;
    PORT
      LAYER M5 ;
        RECT  24.384 0.054 24.408 0.138 ;
    END
  END d[91]
  PIN d[92]
    DIRECTION INPUT ;
    USE SIGNAL ;
    PORT
      LAYER M5 ;
        RECT  24.48 0.054 24.504 0.138 ;
    END
  END d[92]
  PIN d[93]
    DIRECTION INPUT ;
    USE SIGNAL ;
    PORT
      LAYER M5 ;
        RECT  24.576 0.054 24.6 0.138 ;
    END
  END d[93]
  PIN d[94]
    DIRECTION INPUT ;
    USE SIGNAL ;
    PORT
      LAYER M5 ;
        RECT  24.768 0.054 24.792 0.138 ;
    END
  END d[94]
  PIN d[95]
    DIRECTION INPUT ;
    USE SIGNAL ;
    PORT
      LAYER M5 ;
        RECT  24.96 0.054 24.984 0.138 ;
    END
  END d[95]
  PIN d[96]
    DIRECTION INPUT ;
    USE SIGNAL ;
    PORT
      LAYER M5 ;
        RECT  25.152 0.054 25.176 0.138 ;
    END
  END d[96]
  PIN d[97]
    DIRECTION INPUT ;
    USE SIGNAL ;
    PORT
      LAYER M5 ;
        RECT  25.392 0.054 25.416 0.138 ;
    END
  END d[97]
  PIN d[98]
    DIRECTION INPUT ;
    USE SIGNAL ;
    PORT
      LAYER M5 ;
        RECT  25.584 0.054 25.608 0.138 ;
    END
  END d[98]
  PIN d[99]
    DIRECTION INPUT ;
    USE SIGNAL ;
    PORT
      LAYER M5 ;
        RECT  25.776 0.054 25.8 0.138 ;
    END
  END d[99]
  PIN d[9]
    DIRECTION INPUT ;
    USE SIGNAL ;
    PORT
      LAYER M5 ;
        RECT  7.248 0.054 7.272 0.138 ;
    END
  END d[9]
  PIN q[0]
    DIRECTION OUTPUT ;
    USE SIGNAL ;
    PORT
      LAYER M5 ;
        RECT  5.424 14.982 5.448 15.066 ;
    END
  END q[0]
  PIN q[100]
    DIRECTION OUTPUT ;
    USE SIGNAL ;
    PORT
      LAYER M5 ;
        RECT  26.016 14.982 26.04 15.066 ;
    END
  END q[100]
  PIN q[101]
    DIRECTION OUTPUT ;
    USE SIGNAL ;
    PORT
      LAYER M5 ;
        RECT  26.208 14.982 26.232 15.066 ;
    END
  END q[101]
  PIN q[102]
    DIRECTION OUTPUT ;
    USE SIGNAL ;
    PORT
      LAYER M5 ;
        RECT  26.4 14.982 26.424 15.066 ;
    END
  END q[102]
  PIN q[103]
    DIRECTION OUTPUT ;
    USE SIGNAL ;
    PORT
      LAYER M5 ;
        RECT  26.64 14.982 26.664 15.066 ;
    END
  END q[103]
  PIN q[104]
    DIRECTION OUTPUT ;
    USE SIGNAL ;
    PORT
      LAYER M5 ;
        RECT  26.832 14.982 26.856 15.066 ;
    END
  END q[104]
  PIN q[105]
    DIRECTION OUTPUT ;
    USE SIGNAL ;
    PORT
      LAYER M5 ;
        RECT  27.024 14.982 27.048 15.066 ;
    END
  END q[105]
  PIN q[106]
    DIRECTION OUTPUT ;
    USE SIGNAL ;
    PORT
      LAYER M5 ;
        RECT  27.216 14.982 27.24 15.066 ;
    END
  END q[106]
  PIN q[107]
    DIRECTION OUTPUT ;
    USE SIGNAL ;
    PORT
      LAYER M5 ;
        RECT  27.456 14.982 27.48 15.066 ;
    END
  END q[107]
  PIN q[108]
    DIRECTION OUTPUT ;
    USE SIGNAL ;
    PORT
      LAYER M5 ;
        RECT  27.648 14.982 27.672 15.066 ;
    END
  END q[108]
  PIN q[109]
    DIRECTION OUTPUT ;
    USE SIGNAL ;
    PORT
      LAYER M5 ;
        RECT  27.84 14.982 27.864 15.066 ;
    END
  END q[109]
  PIN q[10]
    DIRECTION OUTPUT ;
    USE SIGNAL ;
    PORT
      LAYER M5 ;
        RECT  7.44 14.982 7.464 15.066 ;
    END
  END q[10]
  PIN q[110]
    DIRECTION OUTPUT ;
    USE SIGNAL ;
    PORT
      LAYER M5 ;
        RECT  28.08 14.982 28.104 15.066 ;
    END
  END q[110]
  PIN q[111]
    DIRECTION OUTPUT ;
    USE SIGNAL ;
    PORT
      LAYER M5 ;
        RECT  28.272 14.982 28.296 15.066 ;
    END
  END q[111]
  PIN q[112]
    DIRECTION OUTPUT ;
    USE SIGNAL ;
    PORT
      LAYER M5 ;
        RECT  28.464 14.982 28.488 15.066 ;
    END
  END q[112]
  PIN q[113]
    DIRECTION OUTPUT ;
    USE SIGNAL ;
    PORT
      LAYER M5 ;
        RECT  28.656 14.982 28.68 15.066 ;
    END
  END q[113]
  PIN q[114]
    DIRECTION OUTPUT ;
    USE SIGNAL ;
    PORT
      LAYER M5 ;
        RECT  28.896 14.982 28.92 15.066 ;
    END
  END q[114]
  PIN q[115]
    DIRECTION OUTPUT ;
    USE SIGNAL ;
    PORT
      LAYER M5 ;
        RECT  29.088 14.982 29.112 15.066 ;
    END
  END q[115]
  PIN q[116]
    DIRECTION OUTPUT ;
    USE SIGNAL ;
    PORT
      LAYER M5 ;
        RECT  29.28 14.982 29.304 15.066 ;
    END
  END q[116]
  PIN q[117]
    DIRECTION OUTPUT ;
    USE SIGNAL ;
    PORT
      LAYER M5 ;
        RECT  29.76 14.982 29.784 15.066 ;
    END
  END q[117]
  PIN q[118]
    DIRECTION OUTPUT ;
    USE SIGNAL ;
    PORT
      LAYER M5 ;
        RECT  29.856 14.982 29.88 15.066 ;
    END
  END q[118]
  PIN q[119]
    DIRECTION OUTPUT ;
    USE SIGNAL ;
    PORT
      LAYER M5 ;
        RECT  29.952 14.982 29.976 15.066 ;
    END
  END q[119]
  PIN q[11]
    DIRECTION OUTPUT ;
    USE SIGNAL ;
    PORT
      LAYER M5 ;
        RECT  7.632 14.982 7.656 15.066 ;
    END
  END q[11]
  PIN q[120]
    DIRECTION OUTPUT ;
    USE SIGNAL ;
    PORT
      LAYER M5 ;
        RECT  30.144 14.982 30.168 15.066 ;
    END
  END q[120]
  PIN q[121]
    DIRECTION OUTPUT ;
    USE SIGNAL ;
    PORT
      LAYER M5 ;
        RECT  30.336 14.982 30.36 15.066 ;
    END
  END q[121]
  PIN q[122]
    DIRECTION OUTPUT ;
    USE SIGNAL ;
    PORT
      LAYER M5 ;
        RECT  30.528 14.982 30.552 15.066 ;
    END
  END q[122]
  PIN q[123]
    DIRECTION OUTPUT ;
    USE SIGNAL ;
    PORT
      LAYER M5 ;
        RECT  30.72 14.982 30.744 15.066 ;
    END
  END q[123]
  PIN q[124]
    DIRECTION OUTPUT ;
    USE SIGNAL ;
    PORT
      LAYER M5 ;
        RECT  30.96 14.982 30.984 15.066 ;
    END
  END q[124]
  PIN q[125]
    DIRECTION OUTPUT ;
    USE SIGNAL ;
    PORT
      LAYER M5 ;
        RECT  31.152 14.982 31.176 15.066 ;
    END
  END q[125]
  PIN q[126]
    DIRECTION OUTPUT ;
    USE SIGNAL ;
    PORT
      LAYER M5 ;
        RECT  31.344 14.982 31.368 15.066 ;
    END
  END q[126]
  PIN q[127]
    DIRECTION OUTPUT ;
    USE SIGNAL ;
    PORT
      LAYER M5 ;
        RECT  31.584 14.982 31.608 15.066 ;
    END
  END q[127]
  PIN q[128]
    DIRECTION OUTPUT ;
    USE SIGNAL ;
    PORT
      LAYER M5 ;
        RECT  31.776 14.982 31.8 15.066 ;
    END
  END q[128]
  PIN q[129]
    DIRECTION OUTPUT ;
    USE SIGNAL ;
    PORT
      LAYER M5 ;
        RECT  31.968 14.982 31.992 15.066 ;
    END
  END q[129]
  PIN q[12]
    DIRECTION OUTPUT ;
    USE SIGNAL ;
    PORT
      LAYER M5 ;
        RECT  7.728 14.982 7.752 15.066 ;
    END
  END q[12]
  PIN q[130]
    DIRECTION OUTPUT ;
    USE SIGNAL ;
    PORT
      LAYER M5 ;
        RECT  32.16 14.982 32.184 15.066 ;
    END
  END q[130]
  PIN q[131]
    DIRECTION OUTPUT ;
    USE SIGNAL ;
    PORT
      LAYER M5 ;
        RECT  32.4 14.982 32.424 15.066 ;
    END
  END q[131]
  PIN q[132]
    DIRECTION OUTPUT ;
    USE SIGNAL ;
    PORT
      LAYER M5 ;
        RECT  32.592 14.982 32.616 15.066 ;
    END
  END q[132]
  PIN q[133]
    DIRECTION OUTPUT ;
    USE SIGNAL ;
    PORT
      LAYER M5 ;
        RECT  32.784 14.982 32.808 15.066 ;
    END
  END q[133]
  PIN q[134]
    DIRECTION OUTPUT ;
    USE SIGNAL ;
    PORT
      LAYER M5 ;
        RECT  33.024 14.982 33.048 15.066 ;
    END
  END q[134]
  PIN q[135]
    DIRECTION OUTPUT ;
    USE SIGNAL ;
    PORT
      LAYER M5 ;
        RECT  33.216 14.982 33.24 15.066 ;
    END
  END q[135]
  PIN q[136]
    DIRECTION OUTPUT ;
    USE SIGNAL ;
    PORT
      LAYER M5 ;
        RECT  33.408 14.982 33.432 15.066 ;
    END
  END q[136]
  PIN q[137]
    DIRECTION OUTPUT ;
    USE SIGNAL ;
    PORT
      LAYER M5 ;
        RECT  33.648 14.982 33.672 15.066 ;
    END
  END q[137]
  PIN q[138]
    DIRECTION OUTPUT ;
    USE SIGNAL ;
    PORT
      LAYER M5 ;
        RECT  33.84 14.982 33.864 15.066 ;
    END
  END q[138]
  PIN q[139]
    DIRECTION OUTPUT ;
    USE SIGNAL ;
    PORT
      LAYER M5 ;
        RECT  34.032 14.982 34.056 15.066 ;
    END
  END q[139]
  PIN q[13]
    DIRECTION OUTPUT ;
    USE SIGNAL ;
    PORT
      LAYER M5 ;
        RECT  8.16 14.982 8.184 15.066 ;
    END
  END q[13]
  PIN q[140]
    DIRECTION OUTPUT ;
    USE SIGNAL ;
    PORT
      LAYER M5 ;
        RECT  34.224 14.982 34.248 15.066 ;
    END
  END q[140]
  PIN q[141]
    DIRECTION OUTPUT ;
    USE SIGNAL ;
    PORT
      LAYER M5 ;
        RECT  34.464 14.982 34.488 15.066 ;
    END
  END q[141]
  PIN q[142]
    DIRECTION OUTPUT ;
    USE SIGNAL ;
    PORT
      LAYER M5 ;
        RECT  34.656 14.982 34.68 15.066 ;
    END
  END q[142]
  PIN q[143]
    DIRECTION OUTPUT ;
    USE SIGNAL ;
    PORT
      LAYER M5 ;
        RECT  35.184 14.982 35.208 15.066 ;
    END
  END q[143]
  PIN q[144]
    DIRECTION OUTPUT ;
    USE SIGNAL ;
    PORT
      LAYER M5 ;
        RECT  35.28 14.982 35.304 15.066 ;
    END
  END q[144]
  PIN q[145]
    DIRECTION OUTPUT ;
    USE SIGNAL ;
    PORT
      LAYER M5 ;
        RECT  35.376 14.982 35.4 15.066 ;
    END
  END q[145]
  PIN q[146]
    DIRECTION OUTPUT ;
    USE SIGNAL ;
    PORT
      LAYER M5 ;
        RECT  35.472 14.982 35.496 15.066 ;
    END
  END q[146]
  PIN q[147]
    DIRECTION OUTPUT ;
    USE SIGNAL ;
    PORT
      LAYER M5 ;
        RECT  35.664 14.982 35.688 15.066 ;
    END
  END q[147]
  PIN q[148]
    DIRECTION OUTPUT ;
    USE SIGNAL ;
    PORT
      LAYER M5 ;
        RECT  35.904 14.982 35.928 15.066 ;
    END
  END q[148]
  PIN q[149]
    DIRECTION OUTPUT ;
    USE SIGNAL ;
    PORT
      LAYER M5 ;
        RECT  36.096 14.982 36.12 15.066 ;
    END
  END q[149]
  PIN q[14]
    DIRECTION OUTPUT ;
    USE SIGNAL ;
    PORT
      LAYER M5 ;
        RECT  8.256 14.982 8.28 15.066 ;
    END
  END q[14]
  PIN q[150]
    DIRECTION OUTPUT ;
    USE SIGNAL ;
    PORT
      LAYER M5 ;
        RECT  36.288 14.982 36.312 15.066 ;
    END
  END q[150]
  PIN q[151]
    DIRECTION OUTPUT ;
    USE SIGNAL ;
    PORT
      LAYER M5 ;
        RECT  36.528 14.982 36.552 15.066 ;
    END
  END q[151]
  PIN q[152]
    DIRECTION OUTPUT ;
    USE SIGNAL ;
    PORT
      LAYER M5 ;
        RECT  36.72 14.982 36.744 15.066 ;
    END
  END q[152]
  PIN q[153]
    DIRECTION OUTPUT ;
    USE SIGNAL ;
    PORT
      LAYER M5 ;
        RECT  36.912 14.982 36.936 15.066 ;
    END
  END q[153]
  PIN q[154]
    DIRECTION OUTPUT ;
    USE SIGNAL ;
    PORT
      LAYER M5 ;
        RECT  37.152 14.982 37.176 15.066 ;
    END
  END q[154]
  PIN q[155]
    DIRECTION OUTPUT ;
    USE SIGNAL ;
    PORT
      LAYER M5 ;
        RECT  37.344 14.982 37.368 15.066 ;
    END
  END q[155]
  PIN q[156]
    DIRECTION OUTPUT ;
    USE SIGNAL ;
    PORT
      LAYER M5 ;
        RECT  37.536 14.982 37.56 15.066 ;
    END
  END q[156]
  PIN q[157]
    DIRECTION OUTPUT ;
    USE SIGNAL ;
    PORT
      LAYER M5 ;
        RECT  37.728 14.982 37.752 15.066 ;
    END
  END q[157]
  PIN q[158]
    DIRECTION OUTPUT ;
    USE SIGNAL ;
    PORT
      LAYER M5 ;
        RECT  37.968 14.982 37.992 15.066 ;
    END
  END q[158]
  PIN q[159]
    DIRECTION OUTPUT ;
    USE SIGNAL ;
    PORT
      LAYER M5 ;
        RECT  38.16 14.982 38.184 15.066 ;
    END
  END q[159]
  PIN q[15]
    DIRECTION OUTPUT ;
    USE SIGNAL ;
    PORT
      LAYER M5 ;
        RECT  8.496 14.982 8.52 15.066 ;
    END
  END q[15]
  PIN q[160]
    DIRECTION OUTPUT ;
    USE SIGNAL ;
    PORT
      LAYER M5 ;
        RECT  38.352 14.982 38.376 15.066 ;
    END
  END q[160]
  PIN q[161]
    DIRECTION OUTPUT ;
    USE SIGNAL ;
    PORT
      LAYER M5 ;
        RECT  38.592 14.982 38.616 15.066 ;
    END
  END q[161]
  PIN q[162]
    DIRECTION OUTPUT ;
    USE SIGNAL ;
    PORT
      LAYER M5 ;
        RECT  38.784 14.982 38.808 15.066 ;
    END
  END q[162]
  PIN q[163]
    DIRECTION OUTPUT ;
    USE SIGNAL ;
    PORT
      LAYER M5 ;
        RECT  38.976 14.982 39 15.066 ;
    END
  END q[163]
  PIN q[164]
    DIRECTION OUTPUT ;
    USE SIGNAL ;
    PORT
      LAYER M5 ;
        RECT  39.168 14.982 39.192 15.066 ;
    END
  END q[164]
  PIN q[165]
    DIRECTION OUTPUT ;
    USE SIGNAL ;
    PORT
      LAYER M5 ;
        RECT  39.408 14.982 39.432 15.066 ;
    END
  END q[165]
  PIN q[166]
    DIRECTION OUTPUT ;
    USE SIGNAL ;
    PORT
      LAYER M5 ;
        RECT  39.6 14.982 39.624 15.066 ;
    END
  END q[166]
  PIN q[167]
    DIRECTION OUTPUT ;
    USE SIGNAL ;
    PORT
      LAYER M5 ;
        RECT  39.792 14.982 39.816 15.066 ;
    END
  END q[167]
  PIN q[168]
    DIRECTION OUTPUT ;
    USE SIGNAL ;
    PORT
      LAYER M5 ;
        RECT  40.032 14.982 40.056 15.066 ;
    END
  END q[168]
  PIN q[169]
    DIRECTION OUTPUT ;
    USE SIGNAL ;
    PORT
      LAYER M5 ;
        RECT  40.128 14.982 40.152 15.066 ;
    END
  END q[169]
  PIN q[16]
    DIRECTION OUTPUT ;
    USE SIGNAL ;
    PORT
      LAYER M5 ;
        RECT  8.688 14.982 8.712 15.066 ;
    END
  END q[16]
  PIN q[170]
    DIRECTION OUTPUT ;
    USE SIGNAL ;
    PORT
      LAYER M5 ;
        RECT  40.56 14.982 40.584 15.066 ;
    END
  END q[170]
  PIN q[171]
    DIRECTION OUTPUT ;
    USE SIGNAL ;
    PORT
      LAYER M5 ;
        RECT  40.656 14.982 40.68 15.066 ;
    END
  END q[171]
  PIN q[172]
    DIRECTION OUTPUT ;
    USE SIGNAL ;
    PORT
      LAYER M5 ;
        RECT  40.848 14.982 40.872 15.066 ;
    END
  END q[172]
  PIN q[173]
    DIRECTION OUTPUT ;
    USE SIGNAL ;
    PORT
      LAYER M5 ;
        RECT  41.04 14.982 41.064 15.066 ;
    END
  END q[173]
  PIN q[174]
    DIRECTION OUTPUT ;
    USE SIGNAL ;
    PORT
      LAYER M5 ;
        RECT  41.232 14.982 41.256 15.066 ;
    END
  END q[174]
  PIN q[175]
    DIRECTION OUTPUT ;
    USE SIGNAL ;
    PORT
      LAYER M5 ;
        RECT  41.472 14.982 41.496 15.066 ;
    END
  END q[175]
  PIN q[176]
    DIRECTION OUTPUT ;
    USE SIGNAL ;
    PORT
      LAYER M5 ;
        RECT  41.664 14.982 41.688 15.066 ;
    END
  END q[176]
  PIN q[177]
    DIRECTION OUTPUT ;
    USE SIGNAL ;
    PORT
      LAYER M5 ;
        RECT  41.856 14.982 41.88 15.066 ;
    END
  END q[177]
  PIN q[178]
    DIRECTION OUTPUT ;
    USE SIGNAL ;
    PORT
      LAYER M5 ;
        RECT  42.096 14.982 42.12 15.066 ;
    END
  END q[178]
  PIN q[179]
    DIRECTION OUTPUT ;
    USE SIGNAL ;
    PORT
      LAYER M5 ;
        RECT  42.288 14.982 42.312 15.066 ;
    END
  END q[179]
  PIN q[17]
    DIRECTION OUTPUT ;
    USE SIGNAL ;
    PORT
      LAYER M5 ;
        RECT  8.88 14.982 8.904 15.066 ;
    END
  END q[17]
  PIN q[180]
    DIRECTION OUTPUT ;
    USE SIGNAL ;
    PORT
      LAYER M5 ;
        RECT  42.48 14.982 42.504 15.066 ;
    END
  END q[180]
  PIN q[181]
    DIRECTION OUTPUT ;
    USE SIGNAL ;
    PORT
      LAYER M5 ;
        RECT  42.672 14.982 42.696 15.066 ;
    END
  END q[181]
  PIN q[182]
    DIRECTION OUTPUT ;
    USE SIGNAL ;
    PORT
      LAYER M5 ;
        RECT  42.912 14.982 42.936 15.066 ;
    END
  END q[182]
  PIN q[183]
    DIRECTION OUTPUT ;
    USE SIGNAL ;
    PORT
      LAYER M5 ;
        RECT  43.104 14.982 43.128 15.066 ;
    END
  END q[183]
  PIN q[184]
    DIRECTION OUTPUT ;
    USE SIGNAL ;
    PORT
      LAYER M5 ;
        RECT  43.296 14.982 43.32 15.066 ;
    END
  END q[184]
  PIN q[185]
    DIRECTION OUTPUT ;
    USE SIGNAL ;
    PORT
      LAYER M5 ;
        RECT  43.536 14.982 43.56 15.066 ;
    END
  END q[185]
  PIN q[186]
    DIRECTION OUTPUT ;
    USE SIGNAL ;
    PORT
      LAYER M5 ;
        RECT  43.728 14.982 43.752 15.066 ;
    END
  END q[186]
  PIN q[187]
    DIRECTION OUTPUT ;
    USE SIGNAL ;
    PORT
      LAYER M5 ;
        RECT  43.92 14.982 43.944 15.066 ;
    END
  END q[187]
  PIN q[188]
    DIRECTION OUTPUT ;
    USE SIGNAL ;
    PORT
      LAYER M5 ;
        RECT  44.16 14.982 44.184 15.066 ;
    END
  END q[188]
  PIN q[189]
    DIRECTION OUTPUT ;
    USE SIGNAL ;
    PORT
      LAYER M5 ;
        RECT  44.352 14.982 44.376 15.066 ;
    END
  END q[189]
  PIN q[18]
    DIRECTION OUTPUT ;
    USE SIGNAL ;
    PORT
      LAYER M5 ;
        RECT  9.12 14.982 9.144 15.066 ;
    END
  END q[18]
  PIN q[190]
    DIRECTION OUTPUT ;
    USE SIGNAL ;
    PORT
      LAYER M5 ;
        RECT  44.544 14.982 44.568 15.066 ;
    END
  END q[190]
  PIN q[191]
    DIRECTION OUTPUT ;
    USE SIGNAL ;
    PORT
      LAYER M5 ;
        RECT  44.736 14.982 44.76 15.066 ;
    END
  END q[191]
  PIN q[192]
    DIRECTION OUTPUT ;
    USE SIGNAL ;
    PORT
      LAYER M5 ;
        RECT  44.976 14.982 45 15.066 ;
    END
  END q[192]
  PIN q[193]
    DIRECTION OUTPUT ;
    USE SIGNAL ;
    PORT
      LAYER M5 ;
        RECT  45.168 14.982 45.192 15.066 ;
    END
  END q[193]
  PIN q[194]
    DIRECTION OUTPUT ;
    USE SIGNAL ;
    PORT
      LAYER M5 ;
        RECT  45.36 14.982 45.384 15.066 ;
    END
  END q[194]
  PIN q[195]
    DIRECTION OUTPUT ;
    USE SIGNAL ;
    PORT
      LAYER M5 ;
        RECT  45.504 14.982 45.528 15.066 ;
    END
  END q[195]
  PIN q[196]
    DIRECTION OUTPUT ;
    USE SIGNAL ;
    PORT
      LAYER M5 ;
        RECT  45.984 14.982 46.008 15.066 ;
    END
  END q[196]
  PIN q[197]
    DIRECTION OUTPUT ;
    USE SIGNAL ;
    PORT
      LAYER M5 ;
        RECT  46.08 14.982 46.104 15.066 ;
    END
  END q[197]
  PIN q[198]
    DIRECTION OUTPUT ;
    USE SIGNAL ;
    PORT
      LAYER M5 ;
        RECT  46.176 14.982 46.2 15.066 ;
    END
  END q[198]
  PIN q[199]
    DIRECTION OUTPUT ;
    USE SIGNAL ;
    PORT
      LAYER M5 ;
        RECT  46.416 14.982 46.44 15.066 ;
    END
  END q[199]
  PIN q[19]
    DIRECTION OUTPUT ;
    USE SIGNAL ;
    PORT
      LAYER M5 ;
        RECT  9.312 14.982 9.336 15.066 ;
    END
  END q[19]
  PIN q[1]
    DIRECTION OUTPUT ;
    USE SIGNAL ;
    PORT
      LAYER M5 ;
        RECT  5.616 14.982 5.64 15.066 ;
    END
  END q[1]
  PIN q[200]
    DIRECTION OUTPUT ;
    USE SIGNAL ;
    PORT
      LAYER M5 ;
        RECT  46.608 14.982 46.632 15.066 ;
    END
  END q[200]
  PIN q[201]
    DIRECTION OUTPUT ;
    USE SIGNAL ;
    PORT
      LAYER M5 ;
        RECT  46.8 14.982 46.824 15.066 ;
    END
  END q[201]
  PIN q[202]
    DIRECTION OUTPUT ;
    USE SIGNAL ;
    PORT
      LAYER M5 ;
        RECT  47.04 14.982 47.064 15.066 ;
    END
  END q[202]
  PIN q[203]
    DIRECTION OUTPUT ;
    USE SIGNAL ;
    PORT
      LAYER M5 ;
        RECT  47.232 14.982 47.256 15.066 ;
    END
  END q[203]
  PIN q[204]
    DIRECTION OUTPUT ;
    USE SIGNAL ;
    PORT
      LAYER M5 ;
        RECT  47.424 14.982 47.448 15.066 ;
    END
  END q[204]
  PIN q[205]
    DIRECTION OUTPUT ;
    USE SIGNAL ;
    PORT
      LAYER M5 ;
        RECT  47.616 14.982 47.64 15.066 ;
    END
  END q[205]
  PIN q[206]
    DIRECTION OUTPUT ;
    USE SIGNAL ;
    PORT
      LAYER M5 ;
        RECT  47.856 14.982 47.88 15.066 ;
    END
  END q[206]
  PIN q[207]
    DIRECTION OUTPUT ;
    USE SIGNAL ;
    PORT
      LAYER M5 ;
        RECT  48.048 14.982 48.072 15.066 ;
    END
  END q[207]
  PIN q[208]
    DIRECTION OUTPUT ;
    USE SIGNAL ;
    PORT
      LAYER M5 ;
        RECT  48.24 14.982 48.264 15.066 ;
    END
  END q[208]
  PIN q[209]
    DIRECTION OUTPUT ;
    USE SIGNAL ;
    PORT
      LAYER M5 ;
        RECT  48.48 14.982 48.504 15.066 ;
    END
  END q[209]
  PIN q[20]
    DIRECTION OUTPUT ;
    USE SIGNAL ;
    PORT
      LAYER M5 ;
        RECT  9.504 14.982 9.528 15.066 ;
    END
  END q[20]
  PIN q[210]
    DIRECTION OUTPUT ;
    USE SIGNAL ;
    PORT
      LAYER M5 ;
        RECT  48.672 14.982 48.696 15.066 ;
    END
  END q[210]
  PIN q[211]
    DIRECTION OUTPUT ;
    USE SIGNAL ;
    PORT
      LAYER M5 ;
        RECT  48.864 14.982 48.888 15.066 ;
    END
  END q[211]
  PIN q[212]
    DIRECTION OUTPUT ;
    USE SIGNAL ;
    PORT
      LAYER M5 ;
        RECT  49.104 14.982 49.128 15.066 ;
    END
  END q[212]
  PIN q[213]
    DIRECTION OUTPUT ;
    USE SIGNAL ;
    PORT
      LAYER M5 ;
        RECT  49.296 14.982 49.32 15.066 ;
    END
  END q[213]
  PIN q[214]
    DIRECTION OUTPUT ;
    USE SIGNAL ;
    PORT
      LAYER M5 ;
        RECT  49.488 14.982 49.512 15.066 ;
    END
  END q[214]
  PIN q[215]
    DIRECTION OUTPUT ;
    USE SIGNAL ;
    PORT
      LAYER M5 ;
        RECT  49.68 14.982 49.704 15.066 ;
    END
  END q[215]
  PIN q[216]
    DIRECTION OUTPUT ;
    USE SIGNAL ;
    PORT
      LAYER M5 ;
        RECT  49.92 14.982 49.944 15.066 ;
    END
  END q[216]
  PIN q[217]
    DIRECTION OUTPUT ;
    USE SIGNAL ;
    PORT
      LAYER M5 ;
        RECT  50.112 14.982 50.136 15.066 ;
    END
  END q[217]
  PIN q[218]
    DIRECTION OUTPUT ;
    USE SIGNAL ;
    PORT
      LAYER M5 ;
        RECT  50.304 14.982 50.328 15.066 ;
    END
  END q[218]
  PIN q[219]
    DIRECTION OUTPUT ;
    USE SIGNAL ;
    PORT
      LAYER M5 ;
        RECT  50.544 14.982 50.568 15.066 ;
    END
  END q[219]
  PIN q[21]
    DIRECTION OUTPUT ;
    USE SIGNAL ;
    PORT
      LAYER M5 ;
        RECT  9.696 14.982 9.72 15.066 ;
    END
  END q[21]
  PIN q[220]
    DIRECTION OUTPUT ;
    USE SIGNAL ;
    PORT
      LAYER M5 ;
        RECT  50.736 14.982 50.76 15.066 ;
    END
  END q[220]
  PIN q[221]
    DIRECTION OUTPUT ;
    USE SIGNAL ;
    PORT
      LAYER M5 ;
        RECT  50.928 14.982 50.952 15.066 ;
    END
  END q[221]
  PIN q[222]
    DIRECTION OUTPUT ;
    USE SIGNAL ;
    PORT
      LAYER M5 ;
        RECT  51.36 14.982 51.384 15.066 ;
    END
  END q[222]
  PIN q[223]
    DIRECTION OUTPUT ;
    USE SIGNAL ;
    PORT
      LAYER M5 ;
        RECT  51.456 14.982 51.48 15.066 ;
    END
  END q[223]
  PIN q[224]
    DIRECTION OUTPUT ;
    USE SIGNAL ;
    PORT
      LAYER M5 ;
        RECT  51.552 14.982 51.576 15.066 ;
    END
  END q[224]
  PIN q[225]
    DIRECTION OUTPUT ;
    USE SIGNAL ;
    PORT
      LAYER M5 ;
        RECT  51.744 14.982 51.768 15.066 ;
    END
  END q[225]
  PIN q[226]
    DIRECTION OUTPUT ;
    USE SIGNAL ;
    PORT
      LAYER M5 ;
        RECT  51.984 14.982 52.008 15.066 ;
    END
  END q[226]
  PIN q[227]
    DIRECTION OUTPUT ;
    USE SIGNAL ;
    PORT
      LAYER M5 ;
        RECT  52.176 14.982 52.2 15.066 ;
    END
  END q[227]
  PIN q[228]
    DIRECTION OUTPUT ;
    USE SIGNAL ;
    PORT
      LAYER M5 ;
        RECT  52.368 14.982 52.392 15.066 ;
    END
  END q[228]
  PIN q[229]
    DIRECTION OUTPUT ;
    USE SIGNAL ;
    PORT
      LAYER M5 ;
        RECT  52.608 14.982 52.632 15.066 ;
    END
  END q[229]
  PIN q[22]
    DIRECTION OUTPUT ;
    USE SIGNAL ;
    PORT
      LAYER M5 ;
        RECT  9.936 14.982 9.96 15.066 ;
    END
  END q[22]
  PIN q[230]
    DIRECTION OUTPUT ;
    USE SIGNAL ;
    PORT
      LAYER M5 ;
        RECT  52.8 14.982 52.824 15.066 ;
    END
  END q[230]
  PIN q[231]
    DIRECTION OUTPUT ;
    USE SIGNAL ;
    PORT
      LAYER M5 ;
        RECT  52.992 14.982 53.016 15.066 ;
    END
  END q[231]
  PIN q[232]
    DIRECTION OUTPUT ;
    USE SIGNAL ;
    PORT
      LAYER M5 ;
        RECT  53.184 14.982 53.208 15.066 ;
    END
  END q[232]
  PIN q[233]
    DIRECTION OUTPUT ;
    USE SIGNAL ;
    PORT
      LAYER M5 ;
        RECT  53.424 14.982 53.448 15.066 ;
    END
  END q[233]
  PIN q[234]
    DIRECTION OUTPUT ;
    USE SIGNAL ;
    PORT
      LAYER M5 ;
        RECT  53.616 14.982 53.64 15.066 ;
    END
  END q[234]
  PIN q[235]
    DIRECTION OUTPUT ;
    USE SIGNAL ;
    PORT
      LAYER M5 ;
        RECT  53.808 14.982 53.832 15.066 ;
    END
  END q[235]
  PIN q[236]
    DIRECTION OUTPUT ;
    USE SIGNAL ;
    PORT
      LAYER M5 ;
        RECT  54.048 14.982 54.072 15.066 ;
    END
  END q[236]
  PIN q[237]
    DIRECTION OUTPUT ;
    USE SIGNAL ;
    PORT
      LAYER M5 ;
        RECT  54.24 14.982 54.264 15.066 ;
    END
  END q[237]
  PIN q[238]
    DIRECTION OUTPUT ;
    USE SIGNAL ;
    PORT
      LAYER M5 ;
        RECT  54.432 14.982 54.456 15.066 ;
    END
  END q[238]
  PIN q[239]
    DIRECTION OUTPUT ;
    USE SIGNAL ;
    PORT
      LAYER M5 ;
        RECT  54.624 14.982 54.648 15.066 ;
    END
  END q[239]
  PIN q[23]
    DIRECTION OUTPUT ;
    USE SIGNAL ;
    PORT
      LAYER M5 ;
        RECT  10.128 14.982 10.152 15.066 ;
    END
  END q[23]
  PIN q[240]
    DIRECTION OUTPUT ;
    USE SIGNAL ;
    PORT
      LAYER M5 ;
        RECT  54.864 14.982 54.888 15.066 ;
    END
  END q[240]
  PIN q[241]
    DIRECTION OUTPUT ;
    USE SIGNAL ;
    PORT
      LAYER M5 ;
        RECT  55.056 14.982 55.08 15.066 ;
    END
  END q[241]
  PIN q[242]
    DIRECTION OUTPUT ;
    USE SIGNAL ;
    PORT
      LAYER M5 ;
        RECT  55.248 14.982 55.272 15.066 ;
    END
  END q[242]
  PIN q[243]
    DIRECTION OUTPUT ;
    USE SIGNAL ;
    PORT
      LAYER M5 ;
        RECT  55.488 14.982 55.512 15.066 ;
    END
  END q[243]
  PIN q[244]
    DIRECTION OUTPUT ;
    USE SIGNAL ;
    PORT
      LAYER M5 ;
        RECT  55.68 14.982 55.704 15.066 ;
    END
  END q[244]
  PIN q[245]
    DIRECTION OUTPUT ;
    USE SIGNAL ;
    PORT
      LAYER M5 ;
        RECT  55.872 14.982 55.896 15.066 ;
    END
  END q[245]
  PIN q[246]
    DIRECTION OUTPUT ;
    USE SIGNAL ;
    PORT
      LAYER M5 ;
        RECT  56.112 14.982 56.136 15.066 ;
    END
  END q[246]
  PIN q[247]
    DIRECTION OUTPUT ;
    USE SIGNAL ;
    PORT
      LAYER M5 ;
        RECT  56.304 14.982 56.328 15.066 ;
    END
  END q[247]
  PIN q[248]
    DIRECTION OUTPUT ;
    USE SIGNAL ;
    PORT
      LAYER M5 ;
        RECT  56.784 14.982 56.808 15.066 ;
    END
  END q[248]
  PIN q[249]
    DIRECTION OUTPUT ;
    USE SIGNAL ;
    PORT
      LAYER M5 ;
        RECT  56.88 14.982 56.904 15.066 ;
    END
  END q[249]
  PIN q[24]
    DIRECTION OUTPUT ;
    USE SIGNAL ;
    PORT
      LAYER M5 ;
        RECT  10.32 14.982 10.344 15.066 ;
    END
  END q[24]
  PIN q[250]
    DIRECTION OUTPUT ;
    USE SIGNAL ;
    PORT
      LAYER M5 ;
        RECT  56.976 14.982 57 15.066 ;
    END
  END q[250]
  PIN q[251]
    DIRECTION OUTPUT ;
    USE SIGNAL ;
    PORT
      LAYER M5 ;
        RECT  57.12 14.982 57.144 15.066 ;
    END
  END q[251]
  PIN q[252]
    DIRECTION OUTPUT ;
    USE SIGNAL ;
    PORT
      LAYER M5 ;
        RECT  57.312 14.982 57.336 15.066 ;
    END
  END q[252]
  PIN q[253]
    DIRECTION OUTPUT ;
    USE SIGNAL ;
    PORT
      LAYER M5 ;
        RECT  57.552 14.982 57.576 15.066 ;
    END
  END q[253]
  PIN q[254]
    DIRECTION OUTPUT ;
    USE SIGNAL ;
    PORT
      LAYER M5 ;
        RECT  57.744 14.982 57.768 15.066 ;
    END
  END q[254]
  PIN q[255]
    DIRECTION OUTPUT ;
    USE SIGNAL ;
    PORT
      LAYER M5 ;
        RECT  57.936 14.982 57.96 15.066 ;
    END
  END q[255]
  PIN q[256]
    DIRECTION OUTPUT ;
    USE SIGNAL ;
    PORT
      LAYER M5 ;
        RECT  58.128 14.982 58.152 15.066 ;
    END
  END q[256]
  PIN q[257]
    DIRECTION OUTPUT ;
    USE SIGNAL ;
    PORT
      LAYER M5 ;
        RECT  58.368 14.982 58.392 15.066 ;
    END
  END q[257]
  PIN q[258]
    DIRECTION OUTPUT ;
    USE SIGNAL ;
    PORT
      LAYER M5 ;
        RECT  58.56 14.982 58.584 15.066 ;
    END
  END q[258]
  PIN q[259]
    DIRECTION OUTPUT ;
    USE SIGNAL ;
    PORT
      LAYER M5 ;
        RECT  58.752 14.982 58.776 15.066 ;
    END
  END q[259]
  PIN q[25]
    DIRECTION OUTPUT ;
    USE SIGNAL ;
    PORT
      LAYER M5 ;
        RECT  10.56 14.982 10.584 15.066 ;
    END
  END q[25]
  PIN q[260]
    DIRECTION OUTPUT ;
    USE SIGNAL ;
    PORT
      LAYER M5 ;
        RECT  58.992 14.982 59.016 15.066 ;
    END
  END q[260]
  PIN q[261]
    DIRECTION OUTPUT ;
    USE SIGNAL ;
    PORT
      LAYER M5 ;
        RECT  59.184 14.982 59.208 15.066 ;
    END
  END q[261]
  PIN q[262]
    DIRECTION OUTPUT ;
    USE SIGNAL ;
    PORT
      LAYER M5 ;
        RECT  59.376 14.982 59.4 15.066 ;
    END
  END q[262]
  PIN q[26]
    DIRECTION OUTPUT ;
    USE SIGNAL ;
    PORT
      LAYER M5 ;
        RECT  10.752 14.982 10.776 15.066 ;
    END
  END q[26]
  PIN q[27]
    DIRECTION OUTPUT ;
    USE SIGNAL ;
    PORT
      LAYER M5 ;
        RECT  10.944 14.982 10.968 15.066 ;
    END
  END q[27]
  PIN q[28]
    DIRECTION OUTPUT ;
    USE SIGNAL ;
    PORT
      LAYER M5 ;
        RECT  11.136 14.982 11.16 15.066 ;
    END
  END q[28]
  PIN q[29]
    DIRECTION OUTPUT ;
    USE SIGNAL ;
    PORT
      LAYER M5 ;
        RECT  11.376 14.982 11.4 15.066 ;
    END
  END q[29]
  PIN q[2]
    DIRECTION OUTPUT ;
    USE SIGNAL ;
    PORT
      LAYER M5 ;
        RECT  5.808 14.982 5.832 15.066 ;
    END
  END q[2]
  PIN q[30]
    DIRECTION OUTPUT ;
    USE SIGNAL ;
    PORT
      LAYER M5 ;
        RECT  11.568 14.982 11.592 15.066 ;
    END
  END q[30]
  PIN q[31]
    DIRECTION OUTPUT ;
    USE SIGNAL ;
    PORT
      LAYER M5 ;
        RECT  11.76 14.982 11.784 15.066 ;
    END
  END q[31]
  PIN q[32]
    DIRECTION OUTPUT ;
    USE SIGNAL ;
    PORT
      LAYER M5 ;
        RECT  12 14.982 12.024 15.066 ;
    END
  END q[32]
  PIN q[33]
    DIRECTION OUTPUT ;
    USE SIGNAL ;
    PORT
      LAYER M5 ;
        RECT  12.192 14.982 12.216 15.066 ;
    END
  END q[33]
  PIN q[34]
    DIRECTION OUTPUT ;
    USE SIGNAL ;
    PORT
      LAYER M5 ;
        RECT  12.384 14.982 12.408 15.066 ;
    END
  END q[34]
  PIN q[35]
    DIRECTION OUTPUT ;
    USE SIGNAL ;
    PORT
      LAYER M5 ;
        RECT  12.624 14.982 12.648 15.066 ;
    END
  END q[35]
  PIN q[36]
    DIRECTION OUTPUT ;
    USE SIGNAL ;
    PORT
      LAYER M5 ;
        RECT  12.816 14.982 12.84 15.066 ;
    END
  END q[36]
  PIN q[37]
    DIRECTION OUTPUT ;
    USE SIGNAL ;
    PORT
      LAYER M5 ;
        RECT  13.008 14.982 13.032 15.066 ;
    END
  END q[37]
  PIN q[38]
    DIRECTION OUTPUT ;
    USE SIGNAL ;
    PORT
      LAYER M5 ;
        RECT  13.104 14.982 13.128 15.066 ;
    END
  END q[38]
  PIN q[39]
    DIRECTION OUTPUT ;
    USE SIGNAL ;
    PORT
      LAYER M5 ;
        RECT  13.584 14.982 13.608 15.066 ;
    END
  END q[39]
  PIN q[3]
    DIRECTION OUTPUT ;
    USE SIGNAL ;
    PORT
      LAYER M5 ;
        RECT  6 14.982 6.024 15.066 ;
    END
  END q[3]
  PIN q[40]
    DIRECTION OUTPUT ;
    USE SIGNAL ;
    PORT
      LAYER M5 ;
        RECT  13.68 14.982 13.704 15.066 ;
    END
  END q[40]
  PIN q[41]
    DIRECTION OUTPUT ;
    USE SIGNAL ;
    PORT
      LAYER M5 ;
        RECT  13.824 14.982 13.848 15.066 ;
    END
  END q[41]
  PIN q[42]
    DIRECTION OUTPUT ;
    USE SIGNAL ;
    PORT
      LAYER M5 ;
        RECT  14.064 14.982 14.088 15.066 ;
    END
  END q[42]
  PIN q[43]
    DIRECTION OUTPUT ;
    USE SIGNAL ;
    PORT
      LAYER M5 ;
        RECT  14.256 14.982 14.28 15.066 ;
    END
  END q[43]
  PIN q[44]
    DIRECTION OUTPUT ;
    USE SIGNAL ;
    PORT
      LAYER M5 ;
        RECT  14.448 14.982 14.472 15.066 ;
    END
  END q[44]
  PIN q[45]
    DIRECTION OUTPUT ;
    USE SIGNAL ;
    PORT
      LAYER M5 ;
        RECT  14.64 14.982 14.664 15.066 ;
    END
  END q[45]
  PIN q[46]
    DIRECTION OUTPUT ;
    USE SIGNAL ;
    PORT
      LAYER M5 ;
        RECT  14.88 14.982 14.904 15.066 ;
    END
  END q[46]
  PIN q[47]
    DIRECTION OUTPUT ;
    USE SIGNAL ;
    PORT
      LAYER M5 ;
        RECT  15.072 14.982 15.096 15.066 ;
    END
  END q[47]
  PIN q[48]
    DIRECTION OUTPUT ;
    USE SIGNAL ;
    PORT
      LAYER M5 ;
        RECT  15.264 14.982 15.288 15.066 ;
    END
  END q[48]
  PIN q[49]
    DIRECTION OUTPUT ;
    USE SIGNAL ;
    PORT
      LAYER M5 ;
        RECT  15.504 14.982 15.528 15.066 ;
    END
  END q[49]
  PIN q[4]
    DIRECTION OUTPUT ;
    USE SIGNAL ;
    PORT
      LAYER M5 ;
        RECT  6.192 14.982 6.216 15.066 ;
    END
  END q[4]
  PIN q[50]
    DIRECTION OUTPUT ;
    USE SIGNAL ;
    PORT
      LAYER M5 ;
        RECT  15.696 14.982 15.72 15.066 ;
    END
  END q[50]
  PIN q[51]
    DIRECTION OUTPUT ;
    USE SIGNAL ;
    PORT
      LAYER M5 ;
        RECT  15.888 14.982 15.912 15.066 ;
    END
  END q[51]
  PIN q[52]
    DIRECTION OUTPUT ;
    USE SIGNAL ;
    PORT
      LAYER M5 ;
        RECT  16.128 14.982 16.152 15.066 ;
    END
  END q[52]
  PIN q[53]
    DIRECTION OUTPUT ;
    USE SIGNAL ;
    PORT
      LAYER M5 ;
        RECT  16.32 14.982 16.344 15.066 ;
    END
  END q[53]
  PIN q[54]
    DIRECTION OUTPUT ;
    USE SIGNAL ;
    PORT
      LAYER M5 ;
        RECT  16.512 14.982 16.536 15.066 ;
    END
  END q[54]
  PIN q[55]
    DIRECTION OUTPUT ;
    USE SIGNAL ;
    PORT
      LAYER M5 ;
        RECT  16.704 14.982 16.728 15.066 ;
    END
  END q[55]
  PIN q[56]
    DIRECTION OUTPUT ;
    USE SIGNAL ;
    PORT
      LAYER M5 ;
        RECT  16.944 14.982 16.968 15.066 ;
    END
  END q[56]
  PIN q[57]
    DIRECTION OUTPUT ;
    USE SIGNAL ;
    PORT
      LAYER M5 ;
        RECT  17.136 14.982 17.16 15.066 ;
    END
  END q[57]
  PIN q[58]
    DIRECTION OUTPUT ;
    USE SIGNAL ;
    PORT
      LAYER M5 ;
        RECT  17.328 14.982 17.352 15.066 ;
    END
  END q[58]
  PIN q[59]
    DIRECTION OUTPUT ;
    USE SIGNAL ;
    PORT
      LAYER M5 ;
        RECT  17.568 14.982 17.592 15.066 ;
    END
  END q[59]
  PIN q[5]
    DIRECTION OUTPUT ;
    USE SIGNAL ;
    PORT
      LAYER M5 ;
        RECT  6.432 14.982 6.456 15.066 ;
    END
  END q[5]
  PIN q[60]
    DIRECTION OUTPUT ;
    USE SIGNAL ;
    PORT
      LAYER M5 ;
        RECT  17.76 14.982 17.784 15.066 ;
    END
  END q[60]
  PIN q[61]
    DIRECTION OUTPUT ;
    USE SIGNAL ;
    PORT
      LAYER M5 ;
        RECT  17.952 14.982 17.976 15.066 ;
    END
  END q[61]
  PIN q[62]
    DIRECTION OUTPUT ;
    USE SIGNAL ;
    PORT
      LAYER M5 ;
        RECT  18.144 14.982 18.168 15.066 ;
    END
  END q[62]
  PIN q[63]
    DIRECTION OUTPUT ;
    USE SIGNAL ;
    PORT
      LAYER M5 ;
        RECT  18.384 14.982 18.408 15.066 ;
    END
  END q[63]
  PIN q[64]
    DIRECTION OUTPUT ;
    USE SIGNAL ;
    PORT
      LAYER M5 ;
        RECT  18.528 14.982 18.552 15.066 ;
    END
  END q[64]
  PIN q[65]
    DIRECTION OUTPUT ;
    USE SIGNAL ;
    PORT
      LAYER M5 ;
        RECT  18.96 14.982 18.984 15.066 ;
    END
  END q[65]
  PIN q[66]
    DIRECTION OUTPUT ;
    USE SIGNAL ;
    PORT
      LAYER M5 ;
        RECT  19.056 14.982 19.08 15.066 ;
    END
  END q[66]
  PIN q[67]
    DIRECTION OUTPUT ;
    USE SIGNAL ;
    PORT
      LAYER M5 ;
        RECT  19.2 14.982 19.224 15.066 ;
    END
  END q[67]
  PIN q[68]
    DIRECTION OUTPUT ;
    USE SIGNAL ;
    PORT
      LAYER M5 ;
        RECT  19.392 14.982 19.416 15.066 ;
    END
  END q[68]
  PIN q[69]
    DIRECTION OUTPUT ;
    USE SIGNAL ;
    PORT
      LAYER M5 ;
        RECT  19.632 14.982 19.656 15.066 ;
    END
  END q[69]
  PIN q[6]
    DIRECTION OUTPUT ;
    USE SIGNAL ;
    PORT
      LAYER M5 ;
        RECT  6.624 14.982 6.648 15.066 ;
    END
  END q[6]
  PIN q[70]
    DIRECTION OUTPUT ;
    USE SIGNAL ;
    PORT
      LAYER M5 ;
        RECT  19.824 14.982 19.848 15.066 ;
    END
  END q[70]
  PIN q[71]
    DIRECTION OUTPUT ;
    USE SIGNAL ;
    PORT
      LAYER M5 ;
        RECT  20.016 14.982 20.04 15.066 ;
    END
  END q[71]
  PIN q[72]
    DIRECTION OUTPUT ;
    USE SIGNAL ;
    PORT
      LAYER M5 ;
        RECT  20.208 14.982 20.232 15.066 ;
    END
  END q[72]
  PIN q[73]
    DIRECTION OUTPUT ;
    USE SIGNAL ;
    PORT
      LAYER M5 ;
        RECT  20.448 14.982 20.472 15.066 ;
    END
  END q[73]
  PIN q[74]
    DIRECTION OUTPUT ;
    USE SIGNAL ;
    PORT
      LAYER M5 ;
        RECT  20.64 14.982 20.664 15.066 ;
    END
  END q[74]
  PIN q[75]
    DIRECTION OUTPUT ;
    USE SIGNAL ;
    PORT
      LAYER M5 ;
        RECT  20.832 14.982 20.856 15.066 ;
    END
  END q[75]
  PIN q[76]
    DIRECTION OUTPUT ;
    USE SIGNAL ;
    PORT
      LAYER M5 ;
        RECT  21.072 14.982 21.096 15.066 ;
    END
  END q[76]
  PIN q[77]
    DIRECTION OUTPUT ;
    USE SIGNAL ;
    PORT
      LAYER M5 ;
        RECT  21.264 14.982 21.288 15.066 ;
    END
  END q[77]
  PIN q[78]
    DIRECTION OUTPUT ;
    USE SIGNAL ;
    PORT
      LAYER M5 ;
        RECT  21.456 14.982 21.48 15.066 ;
    END
  END q[78]
  PIN q[79]
    DIRECTION OUTPUT ;
    USE SIGNAL ;
    PORT
      LAYER M5 ;
        RECT  21.648 14.982 21.672 15.066 ;
    END
  END q[79]
  PIN q[7]
    DIRECTION OUTPUT ;
    USE SIGNAL ;
    PORT
      LAYER M5 ;
        RECT  6.816 14.982 6.84 15.066 ;
    END
  END q[7]
  PIN q[80]
    DIRECTION OUTPUT ;
    USE SIGNAL ;
    PORT
      LAYER M5 ;
        RECT  21.888 14.982 21.912 15.066 ;
    END
  END q[80]
  PIN q[81]
    DIRECTION OUTPUT ;
    USE SIGNAL ;
    PORT
      LAYER M5 ;
        RECT  22.08 14.982 22.104 15.066 ;
    END
  END q[81]
  PIN q[82]
    DIRECTION OUTPUT ;
    USE SIGNAL ;
    PORT
      LAYER M5 ;
        RECT  22.272 14.982 22.296 15.066 ;
    END
  END q[82]
  PIN q[83]
    DIRECTION OUTPUT ;
    USE SIGNAL ;
    PORT
      LAYER M5 ;
        RECT  22.512 14.982 22.536 15.066 ;
    END
  END q[83]
  PIN q[84]
    DIRECTION OUTPUT ;
    USE SIGNAL ;
    PORT
      LAYER M5 ;
        RECT  22.704 14.982 22.728 15.066 ;
    END
  END q[84]
  PIN q[85]
    DIRECTION OUTPUT ;
    USE SIGNAL ;
    PORT
      LAYER M5 ;
        RECT  22.896 14.982 22.92 15.066 ;
    END
  END q[85]
  PIN q[86]
    DIRECTION OUTPUT ;
    USE SIGNAL ;
    PORT
      LAYER M5 ;
        RECT  23.136 14.982 23.16 15.066 ;
    END
  END q[86]
  PIN q[87]
    DIRECTION OUTPUT ;
    USE SIGNAL ;
    PORT
      LAYER M5 ;
        RECT  23.328 14.982 23.352 15.066 ;
    END
  END q[87]
  PIN q[88]
    DIRECTION OUTPUT ;
    USE SIGNAL ;
    PORT
      LAYER M5 ;
        RECT  23.52 14.982 23.544 15.066 ;
    END
  END q[88]
  PIN q[89]
    DIRECTION OUTPUT ;
    USE SIGNAL ;
    PORT
      LAYER M5 ;
        RECT  23.712 14.982 23.736 15.066 ;
    END
  END q[89]
  PIN q[8]
    DIRECTION OUTPUT ;
    USE SIGNAL ;
    PORT
      LAYER M5 ;
        RECT  7.056 14.982 7.08 15.066 ;
    END
  END q[8]
  PIN q[90]
    DIRECTION OUTPUT ;
    USE SIGNAL ;
    PORT
      LAYER M5 ;
        RECT  23.904 14.982 23.928 15.066 ;
    END
  END q[90]
  PIN q[91]
    DIRECTION OUTPUT ;
    USE SIGNAL ;
    PORT
      LAYER M5 ;
        RECT  24.384 14.982 24.408 15.066 ;
    END
  END q[91]
  PIN q[92]
    DIRECTION OUTPUT ;
    USE SIGNAL ;
    PORT
      LAYER M5 ;
        RECT  24.48 14.982 24.504 15.066 ;
    END
  END q[92]
  PIN q[93]
    DIRECTION OUTPUT ;
    USE SIGNAL ;
    PORT
      LAYER M5 ;
        RECT  24.576 14.982 24.6 15.066 ;
    END
  END q[93]
  PIN q[94]
    DIRECTION OUTPUT ;
    USE SIGNAL ;
    PORT
      LAYER M5 ;
        RECT  24.768 14.982 24.792 15.066 ;
    END
  END q[94]
  PIN q[95]
    DIRECTION OUTPUT ;
    USE SIGNAL ;
    PORT
      LAYER M5 ;
        RECT  24.96 14.982 24.984 15.066 ;
    END
  END q[95]
  PIN q[96]
    DIRECTION OUTPUT ;
    USE SIGNAL ;
    PORT
      LAYER M5 ;
        RECT  25.152 14.982 25.176 15.066 ;
    END
  END q[96]
  PIN q[97]
    DIRECTION OUTPUT ;
    USE SIGNAL ;
    PORT
      LAYER M5 ;
        RECT  25.392 14.982 25.416 15.066 ;
    END
  END q[97]
  PIN q[98]
    DIRECTION OUTPUT ;
    USE SIGNAL ;
    PORT
      LAYER M5 ;
        RECT  25.584 14.982 25.608 15.066 ;
    END
  END q[98]
  PIN q[99]
    DIRECTION OUTPUT ;
    USE SIGNAL ;
    PORT
      LAYER M5 ;
        RECT  25.776 14.982 25.8 15.066 ;
    END
  END q[99]
  PIN q[9]
    DIRECTION OUTPUT ;
    USE SIGNAL ;
    PORT
      LAYER M5 ;
        RECT  7.248 14.982 7.272 15.066 ;
    END
  END q[9]
  PIN rst_n
    DIRECTION INPUT ;
    USE SIGNAL ;
    PORT
      LAYER M4 ;
        RECT  0.054 9.696 0.138 9.72 ;
    END
    PORT
      LAYER M4 ;
        RECT  0.108 9.696 0.569 9.72 ;
    END
  END rst_n
  PIN VDD
    DIRECTION INOUT ;
    USE POWER ;
    PORT
      LAYER M5 ;
        RECT  61.992 2.151 62.112 12.969 ;
        RECT  56.592 2.151 56.712 12.969 ;
        RECT  51.192 2.151 51.312 12.969 ;
        RECT  45.792 2.151 45.912 12.969 ;
        RECT  40.392 2.151 40.512 12.969 ;
        RECT  34.992 2.151 35.112 12.969 ;
        RECT  29.592 2.151 29.712 12.969 ;
        RECT  24.192 2.151 24.312 12.969 ;
        RECT  18.792 2.151 18.912 12.969 ;
        RECT  13.392 2.151 13.512 12.969 ;
        RECT  7.992 2.151 8.112 12.969 ;
        RECT  2.592 2.151 2.712 12.969 ;
    END
  END VDD
  PIN VSS
    DIRECTION INOUT ;
    USE GROUND ;
    PORT
      LAYER M5 ;
        RECT  61.8 2.137 61.92 12.983 ;
        RECT  56.4 2.137 56.52 12.983 ;
        RECT  51 2.137 51.12 12.983 ;
        RECT  45.6 2.137 45.72 12.983 ;
        RECT  40.2 2.137 40.32 12.983 ;
        RECT  34.8 2.137 34.92 12.983 ;
        RECT  29.4 2.137 29.52 12.983 ;
        RECT  24 2.137 24.12 12.983 ;
        RECT  18.6 2.137 18.72 12.983 ;
        RECT  13.2 2.137 13.32 12.983 ;
        RECT  7.8 2.137 7.92 12.983 ;
        RECT  2.4 2.137 2.52 12.983 ;
    END
  END VSS
  # OT_OBS_CLOSED layer=M5 d_um=1.536 added=68
  OBS
    LAYER RVTN ;
     RECT  2.16 2.16 62.64 2.295 ;
     RECT  2.16 2.565 62.64 2.835 ;
     RECT  2.16 3.105 62.64 3.375 ;
     RECT  2.16 3.645 62.64 3.915 ;
     RECT  2.16 4.185 62.64 4.455 ;
     RECT  2.16 4.725 62.64 4.995 ;
     RECT  2.16 5.265 62.64 5.535 ;
     RECT  2.16 5.805 62.64 6.075 ;
     RECT  2.16 6.345 62.64 6.615 ;
     RECT  2.16 6.885 62.64 7.155 ;
     RECT  2.16 7.425 62.64 7.695 ;
     RECT  2.16 7.965 62.64 8.235 ;
     RECT  2.16 8.505 62.64 8.775 ;
     RECT  2.16 9.045 62.64 9.315 ;
     RECT  2.16 9.585 62.64 9.855 ;
     RECT  2.16 10.125 62.64 10.395 ;
     RECT  2.16 10.665 62.64 10.935 ;
     RECT  2.16 11.205 62.64 11.475 ;
     RECT  2.16 11.745 62.64 12.015 ;
     RECT  2.16 12.285 62.64 12.555 ;
     RECT  2.16 12.825 62.64 12.96 ;
    LAYER RVTP ;
     RECT  2.16 2.295 62.64 2.565 ;
     RECT  2.16 2.835 62.64 3.105 ;
     RECT  2.16 3.375 62.64 3.645 ;
     RECT  2.16 3.915 62.64 4.185 ;
     RECT  2.16 4.455 62.64 4.725 ;
     RECT  2.16 4.995 62.64 5.265 ;
     RECT  2.16 5.535 62.64 5.805 ;
     RECT  2.16 6.075 62.64 6.345 ;
     RECT  2.16 6.615 62.64 6.885 ;
     RECT  2.16 7.155 62.64 7.425 ;
     RECT  2.16 7.695 62.64 7.965 ;
     RECT  2.16 8.235 62.64 8.505 ;
     RECT  2.16 8.775 62.64 9.045 ;
     RECT  2.16 9.315 62.64 9.585 ;
     RECT  2.16 9.855 62.64 10.125 ;
     RECT  2.16 10.395 62.64 10.665 ;
     RECT  2.16 10.935 62.64 11.205 ;
     RECT  2.16 11.475 62.64 11.745 ;
     RECT  2.16 12.015 62.64 12.285 ;
     RECT  2.16 12.555 62.64 12.825 ;
    LAYER M1 ;
     RECT  2.16 2.151 62.64 12.969 ;
    LAYER M2 ;
     RECT  0.535 9.252 2.16 9.27 ;
     RECT  2.16 2.151 42.691 12.969 ;
     RECT  42.691 2.106 43.043 12.969 ;
     RECT  43.043 2.151 48.559 12.969 ;
     RECT  48.559 2.106 48.767 12.969 ;
     RECT  48.767 2.151 55.579 12.969 ;
     RECT  55.579 2.106 55.895 12.969 ;
     RECT  55.895 2.151 62.64 12.969 ;
    LAYER M3 ;
     RECT  26.352 0.523 26.37 0.571 ;
     RECT  31.572 0.523 31.59 0.571 ;
     RECT  51.336 0.139 51.354 0.571 ;
     RECT  34.776 0.571 34.794 1.099 ;
     RECT  35.82 0.139 35.838 1.099 ;
     RECT  39.996 0.571 40.014 1.099 ;
     RECT  15.66 0.139 15.678 1.627 ;
     RECT  34.776 1.099 35.838 1.675 ;
     RECT  50.724 0.571 51.354 1.675 ;
     RECT  52.38 0.139 52.398 1.675 ;
     RECT  9 1.099 9.018 1.723 ;
     RECT  10.368 1.147 10.386 1.723 ;
     RECT  11.304 0.139 11.322 1.723 ;
     RECT  12.384 1.147 12.402 1.723 ;
     RECT  14.256 0.523 14.634 1.723 ;
     RECT  15.66 1.627 15.894 1.723 ;
     RECT  17.136 0.571 17.154 1.723 ;
     RECT  18.576 1.675 18.594 1.723 ;
     RECT  19.692 0.139 19.71 1.723 ;
     RECT  24.444 1.099 24.462 1.723 ;
     RECT  26.244 0.571 26.37 1.723 ;
     RECT  29.556 0.139 29.574 1.723 ;
     RECT  31.572 0.571 31.986 1.723 ;
     RECT  34.776 1.675 36.486 1.723 ;
     RECT  39.888 1.099 40.014 1.723 ;
     RECT  40.788 1.675 40.806 1.723 ;
     RECT  41.652 0.571 41.67 1.723 ;
     RECT  42.876 0.571 42.894 1.723 ;
     RECT  43.74 0.139 43.758 1.723 ;
     RECT  46.188 0.571 46.206 1.723 ;
     RECT  48.492 0.139 49.122 1.723 ;
     RECT  50.724 1.675 52.398 1.723 ;
     RECT  54.828 0.523 54.846 1.723 ;
     RECT  55.872 0.571 55.89 1.723 ;
     RECT  58.14 0.571 58.158 1.723 ;
     RECT  59.364 0.571 59.382 1.723 ;
     RECT  5.436 1.723 11.394 1.771 ;
     RECT  43.668 1.723 52.578 1.771 ;
     RECT  53.568 1.723 59.382 1.771 ;
     RECT  16.668 1.723 42.894 2.101 ;
     RECT  43.668 1.771 59.382 2.101 ;
     RECT  16.668 2.101 59.382 2.191 ;
     RECT  5.364 1.771 11.394 2.203 ;
     RECT  12.384 1.723 15.93 2.203 ;
     RECT  5.364 2.203 15.93 2.251 ;
     RECT  16.668 2.191 60.03 2.251 ;
     RECT  5.364 2.251 60.03 2.299 ;
     RECT  5.364 2.299 60.174 2.335 ;
     RECT  5.364 2.335 60.714 2.371 ;
     RECT  61.815 2.143 61.905 2.371 ;
     RECT  2.415 2.143 2.505 2.413 ;
     RECT  5.364 2.371 61.905 2.413 ;
     RECT  5.364 2.413 62.097 3.379 ;
     RECT  5.112 3.379 62.097 3.983 ;
     RECT  5.652 3.983 62.097 4.289 ;
     RECT  5.868 4.289 62.097 5.131 ;
     RECT  5.292 5.131 62.097 5.189 ;
     RECT  5.868 5.189 62.097 5.369 ;
     RECT  6.084 5.369 62.097 6.107 ;
     RECT  6.084 6.107 60.498 6.179 ;
     RECT  6.084 6.179 60.354 6.305 ;
     RECT  6.084 6.305 60.21 6.809 ;
     RECT  6.084 6.809 49.698 7.421 ;
     RECT  6.084 7.421 38.07 7.619 ;
     RECT  38.808 7.421 49.698 7.619 ;
     RECT  0.54 9.247 0.558 9.725 ;
     RECT  6.084 7.619 30.438 10.471 ;
     RECT  31.176 7.619 38.07 10.471 ;
     RECT  6.084 10.471 38.07 10.741 ;
     RECT  38.844 7.619 49.698 10.741 ;
     RECT  50.436 6.809 60.21 10.741 ;
     RECT  5.112 5.503 5.13 11.371 ;
     RECT  6.084 10.741 60.21 11.371 ;
     RECT  5.112 11.371 60.21 11.399 ;
     RECT  5.292 11.399 60.21 11.515 ;
     RECT  5.292 11.515 60.39 11.669 ;
     RECT  5.292 11.669 59.958 12.317 ;
     RECT  5.292 12.317 59.922 12.551 ;
     RECT  2.415 2.413 2.697 12.707 ;
     RECT  61.815 6.107 62.097 12.707 ;
     RECT  5.292 12.551 59.85 12.785 ;
     RECT  5.436 12.785 59.85 12.929 ;
     RECT  2.415 12.707 2.505 12.977 ;
     RECT  5.436 12.929 59.022 12.977 ;
     RECT  61.815 12.707 61.905 12.977 ;
     RECT  5.436 12.977 50.886 13.085 ;
     RECT  51.624 12.977 59.022 13.085 ;
     RECT  59.832 12.929 59.85 13.085 ;
     RECT  16.992 13.085 23.67 13.133 ;
     RECT  7.236 13.085 16.218 13.661 ;
     RECT  23.148 13.133 23.67 13.661 ;
     RECT  24.696 13.085 34.722 13.661 ;
     RECT  36.216 13.085 50.886 13.661 ;
     RECT  51.624 13.085 57.474 13.661 ;
     RECT  58.5 13.085 59.022 13.661 ;
     RECT  47.52 13.661 50.886 13.709 ;
     RECT  16.992 13.133 22.302 14.189 ;
     RECT  5.436 13.085 6.462 14.237 ;
     RECT  7.236 13.661 7.758 14.237 ;
     RECT  9.108 13.661 11.178 14.237 ;
     RECT  12.384 13.661 16.218 14.237 ;
     RECT  16.992 14.189 20.142 14.237 ;
     RECT  20.916 14.189 22.302 14.237 ;
     RECT  23.184 13.661 23.67 14.237 ;
     RECT  24.876 13.661 25.29 14.237 ;
     RECT  26.388 13.661 29.97 14.237 ;
     RECT  30.708 13.661 34.722 14.237 ;
     RECT  36.216 13.661 39.078 14.237 ;
     RECT  41.652 13.661 46.71 14.237 ;
     RECT  47.52 13.709 50.85 14.237 ;
     RECT  52.344 13.661 57.474 14.237 ;
     RECT  58.968 13.661 58.986 14.237 ;
     RECT  12.888 14.237 13.59 14.285 ;
     RECT  26.388 14.237 28.962 14.285 ;
     RECT  49.464 14.237 50.85 14.285 ;
     RECT  49.464 14.285 49.734 14.765 ;
     RECT  54 14.237 54.666 14.909 ;
     RECT  6.444 14.237 6.462 14.957 ;
     RECT  9.108 14.237 9.126 14.957 ;
     RECT  9.936 14.237 11.178 14.957 ;
     RECT  12.888 14.285 12.906 14.957 ;
     RECT  16.2 14.237 16.218 14.957 ;
     RECT  17.64 14.237 18.162 14.957 ;
     RECT  19.656 14.237 19.674 14.957 ;
     RECT  20.916 14.237 21.402 14.957 ;
     RECT  22.176 14.237 22.194 14.957 ;
     RECT  26.388 14.285 26.406 14.957 ;
     RECT  27.648 14.285 28.962 14.957 ;
     RECT  29.772 14.237 29.79 14.957 ;
     RECT  30.708 14.237 30.726 14.957 ;
     RECT  31.572 14.237 33.282 14.957 ;
     RECT  34.056 14.237 34.722 14.957 ;
     RECT  36.216 14.237 37.998 14.957 ;
     RECT  39.06 14.237 39.078 14.957 ;
     RECT  39.888 13.661 40.446 14.957 ;
     RECT  42.012 14.237 42.966 14.957 ;
     RECT  43.74 14.237 43.974 14.957 ;
     RECT  44.82 14.237 45.378 14.957 ;
     RECT  46.692 14.237 46.71 14.957 ;
     RECT  47.52 14.237 47.538 14.957 ;
     RECT  48.672 14.237 48.69 14.957 ;
     RECT  49.716 14.765 49.734 14.957 ;
     RECT  50.832 14.285 50.85 14.957 ;
     RECT  52.344 14.237 52.938 14.957 ;
     RECT  54 14.909 54.45 14.957 ;
     RECT  55.728 14.237 56.106 14.957 ;
     RECT  57.384 14.237 57.402 14.957 ;
    LAYER M4 ;
     RECT  0.179 4.416 2.408 4.44 ;
     RECT  2.408 2.148 2.512 12.972 ;
     RECT  2.512 2.418 2.704 12.702 ;
     RECT  2.704 4.416 5.281 4.44 ;
     RECT  5.353 1.776 5.381 1.8 ;
     RECT  5.381 1.728 5.785 1.8 ;
     RECT  5.605 13.056 5.957 13.08 ;
     RECT  5.381 14.208 5.957 14.232 ;
     RECT  5.957 13.056 6.041 14.232 ;
     RECT  5.461 3.312 6.073 3.336 ;
     RECT  5.281 4.416 6.073 5.16 ;
     RECT  6.041 14.208 6.389 14.232 ;
     RECT  6.389 14.208 6.473 14.952 ;
     RECT  6.073 3.312 6.545 5.16 ;
     RECT  6.041 13.056 6.764 13.08 ;
     RECT  6.545 3.6 6.937 5.16 ;
     RECT  6.764 12.528 7.613 13.08 ;
     RECT  6.473 14.208 7.613 14.232 ;
     RECT  6.937 3.6 7.729 5.208 ;
     RECT  7.613 12.528 7.769 14.232 ;
     RECT  5.785 1.728 7.808 1.848 ;
     RECT  7.729 3.6 7.808 5.592 ;
     RECT  7.769 12.528 7.808 13.656 ;
     RECT  7.808 1.728 8.104 13.656 ;
     RECT  8.104 1.728 8.723 1.8 ;
     RECT  8.723 1.728 8.989 1.752 ;
     RECT  8.104 12.528 9.029 13.656 ;
     RECT  8.989 1.104 9.155 1.752 ;
     RECT  9.029 13.056 9.493 13.656 ;
     RECT  9.097 14.928 9.493 14.952 ;
     RECT  9.493 13.056 9.641 14.952 ;
     RECT  8.104 3.6 9.673 5.784 ;
     RECT  9.641 13.68 9.731 14.952 ;
     RECT  9.673 3.12 10.249 5.784 ;
     RECT  9.155 1.728 10.357 1.752 ;
     RECT  10.249 2.88 10.397 5.784 ;
     RECT  10.397 2.88 10.595 5.736 ;
     RECT  9.731 14.16 10.787 14.952 ;
     RECT  10.717 6.816 10.829 6.84 ;
     RECT  10.357 1.152 10.979 1.752 ;
     RECT  10.787 14.928 11.189 14.952 ;
     RECT  10.933 13.632 11.329 13.656 ;
     RECT  10.979 1.728 11.365 1.752 ;
     RECT  10.595 2.88 11.365 5.592 ;
     RECT  11.365 1.728 11.411 5.592 ;
     RECT  11.411 1.728 11.441 3.432 ;
     RECT  11.293 0.144 11.603 0.168 ;
     RECT  11.329 13.056 11.945 13.656 ;
     RECT  11.441 1.728 12.035 2.904 ;
     RECT  12.035 1.728 12.373 1.752 ;
     RECT  11.989 14.208 12.413 14.232 ;
     RECT  12.373 1.152 12.457 1.752 ;
     RECT  11.411 4.416 12.877 5.592 ;
     RECT  12.613 14.928 12.917 14.952 ;
     RECT  11.945 13.056 12.985 13.128 ;
     RECT  12.035 2.88 13.004 2.904 ;
     RECT  12.457 1.728 13.052 1.752 ;
     RECT  13.004 2.88 13.052 3.24 ;
     RECT  12.985 13.008 13.093 13.128 ;
     RECT  13.093 13.008 13.177 13.656 ;
     RECT  13.052 1.728 13.208 3.24 ;
     RECT  12.877 4.416 13.208 6.072 ;
     RECT  13.177 13.008 13.208 13.08 ;
     RECT  13.208 1.728 13.504 13.08 ;
     RECT  13.561 14.256 13.859 14.28 ;
     RECT  13.504 12.528 14.141 13.08 ;
     RECT  13.504 1.728 14.485 2.904 ;
     RECT  14.485 1.728 14.675 3.144 ;
     RECT  14.675 2.736 14.713 3.144 ;
     RECT  13.504 4.416 14.713 6.888 ;
     RECT  14.141 12.528 14.825 12.552 ;
     RECT  14.204 0.528 14.915 0.552 ;
     RECT  14.713 2.736 14.969 6.888 ;
     RECT  14.209 14.208 15.545 14.232 ;
     RECT  15.253 13.056 15.685 13.08 ;
     RECT  15.493 0.144 15.689 0.168 ;
     RECT  14.675 1.728 15.865 1.752 ;
     RECT  15.685 13.056 15.869 13.656 ;
     RECT  16.045 10.848 16.157 10.872 ;
     RECT  15.865 1.632 16.163 1.752 ;
     RECT  16.163 1.728 16.225 1.752 ;
     RECT  14.969 2.736 16.225 6.168 ;
     RECT  16.117 14.928 16.229 14.952 ;
     RECT  15.869 13.056 16.289 13.08 ;
     RECT  16.289 12.288 16.373 13.08 ;
     RECT  16.225 1.728 16.547 6.168 ;
     RECT  16.373 12.528 16.561 13.08 ;
     RECT  16.561 12.528 16.877 12.552 ;
     RECT  16.547 3.024 17.129 6.168 ;
     RECT  17.125 0.576 17.209 0.6 ;
     RECT  16.933 14.208 17.317 14.232 ;
     RECT  17.129 3.408 17.341 6.168 ;
     RECT  17.341 3.408 17.453 6.84 ;
     RECT  16.547 1.728 17.516 1.752 ;
     RECT  17.557 13.056 17.641 13.08 ;
     RECT  17.317 14.208 17.941 14.952 ;
     RECT  17.941 13.632 18.029 14.952 ;
     RECT  18.029 14.208 18.217 14.952 ;
     RECT  17.516 1.728 18.565 2.28 ;
     RECT  18.565 1.68 18.608 2.28 ;
     RECT  17.453 3.408 18.608 6.168 ;
     RECT  18.608 1.68 18.904 12.972 ;
     RECT  18.904 1.68 18.995 1.848 ;
     RECT  18.217 14.208 19.045 14.232 ;
     RECT  18.904 3.408 19.073 6.168 ;
     RECT  19.045 13.056 19.253 14.232 ;
     RECT  19.253 14.16 19.601 14.232 ;
     RECT  18.995 1.728 19.865 1.848 ;
     RECT  19.253 13.056 19.937 13.08 ;
     RECT  19.681 0.144 20.051 0.168 ;
     RECT  19.073 3.936 20.257 6.168 ;
     RECT  20.429 12.768 20.513 12.792 ;
     RECT  20.257 3.408 20.837 6.168 ;
     RECT  19.865 1.728 21.107 1.8 ;
     RECT  20.837 3.408 21.107 5.736 ;
     RECT  21.049 13.056 21.133 13.08 ;
     RECT  19.601 14.16 21.445 14.952 ;
     RECT  21.445 13.632 21.557 14.952 ;
     RECT  21.877 12.192 22.061 12.216 ;
     RECT  21.557 14.208 22.205 14.952 ;
     RECT  22.453 12.528 22.739 13.128 ;
     RECT  21.107 1.728 22.813 1.752 ;
     RECT  22.739 13.056 23.093 13.128 ;
     RECT  22.205 14.208 23.093 14.232 ;
     RECT  23.093 13.056 23.177 14.232 ;
     RECT  21.107 3.408 23.269 5.544 ;
     RECT  23.177 13.056 23.857 13.08 ;
     RECT  22.813 1.728 24.008 1.848 ;
     RECT  23.269 2.832 24.008 5.544 ;
     RECT  23.857 12.96 24.008 13.08 ;
     RECT  24.008 1.728 24.304 13.08 ;
     RECT  24.304 2.832 24.401 5.736 ;
     RECT  24.304 1.728 24.433 1.8 ;
     RECT  24.304 12 24.515 12.024 ;
     RECT  24.433 1.104 24.611 1.8 ;
     RECT  24.401 3.84 24.659 5.736 ;
     RECT  24.401 2.832 24.661 2.856 ;
     RECT  24.304 13.056 24.685 13.08 ;
     RECT  23.177 14.208 24.685 14.232 ;
     RECT  24.685 13.056 25.301 14.232 ;
     RECT  24.659 3.84 25.657 5.544 ;
     RECT  25.301 13.056 25.661 13.656 ;
     RECT  24.611 1.728 25.724 1.8 ;
     RECT  25.724 1.728 25.811 2.28 ;
     RECT  25.657 3.408 25.981 5.544 ;
     RECT  25.981 2.88 26.093 5.544 ;
     RECT  26.189 0.576 26.273 0.6 ;
     RECT  26.197 14.928 26.417 14.952 ;
     RECT  26.341 0.528 26.435 0.552 ;
     RECT  25.661 13.536 26.629 13.656 ;
     RECT  26.629 12.912 26.777 13.656 ;
     RECT  26.777 12.912 26.821 13.08 ;
     RECT  26.821 12.528 27.245 13.08 ;
     RECT  25.811 1.728 27.404 1.8 ;
     RECT  26.953 14.208 27.445 14.28 ;
     RECT  27.404 1.728 27.491 2.28 ;
     RECT  26.093 3.408 27.529 5.544 ;
     RECT  27.445 14.208 27.713 14.952 ;
     RECT  27.491 1.728 27.875 1.8 ;
     RECT  27.529 2.88 28.429 5.544 ;
     RECT  26.581 6.528 28.429 6.552 ;
     RECT  27.245 13.056 28.937 13.08 ;
     RECT  27.713 14.928 29.077 14.952 ;
     RECT  27.875 1.728 29.113 1.752 ;
     RECT  29.113 1.728 29.408 1.848 ;
     RECT  28.429 2.88 29.408 6.552 ;
     RECT  29.249 12.528 29.408 12.972 ;
     RECT  29.408 1.728 29.704 12.972 ;
     RECT  29.545 0.144 29.795 0.168 ;
     RECT  29.704 3.84 29.873 5.784 ;
     RECT  29.933 13.056 30.325 13.08 ;
     RECT  29.077 14.208 30.325 14.952 ;
     RECT  30.325 13.056 30.521 14.952 ;
     RECT  29.704 1.728 30.845 2.856 ;
     RECT  29.873 3.936 30.845 5.784 ;
     RECT  30.845 4.128 31.093 5.784 ;
     RECT  30.521 13.056 31.349 13.08 ;
     RECT  31.532 0.528 31.619 0.552 ;
     RECT  30.521 14.208 31.633 14.952 ;
     RECT  31.093 4.128 31.637 6.648 ;
     RECT  30.845 1.728 31.813 2.712 ;
     RECT  31.957 0.576 32.041 0.6 ;
     RECT  31.633 13.68 32.389 14.952 ;
     RECT  31.813 1.728 32.435 2.808 ;
     RECT  32.389 13.632 32.473 14.952 ;
     RECT  31.637 4.128 32.483 4.536 ;
     RECT  32.483 4.32 32.641 4.536 ;
     RECT  31.637 5.76 32.641 6.648 ;
     RECT  32.641 4.32 32.749 6.648 ;
     RECT  32.749 4.32 32.897 7.464 ;
     RECT  32.897 4.512 32.915 7.464 ;
     RECT  32.915 4.512 33.059 5.16 ;
     RECT  32.437 3.072 33.073 3.096 ;
     RECT  33.073 3.072 33.185 3.192 ;
     RECT  32.473 14.208 34.265 14.952 ;
     RECT  33.059 4.512 34.513 4.728 ;
     RECT  33.185 3.072 34.621 3.096 ;
     RECT  34.513 4.512 34.621 5.016 ;
     RECT  34.265 14.928 34.733 14.952 ;
     RECT  32.435 1.728 34.808 1.752 ;
     RECT  34.621 3.072 34.808 5.016 ;
     RECT  32.915 6.624 34.808 6.648 ;
     RECT  33.001 13.056 34.808 13.08 ;
     RECT  34.808 1.728 35.104 13.08 ;
     RECT  35.104 1.728 35.219 6.648 ;
     RECT  34.765 0.576 35.233 0.6 ;
     RECT  35.219 1.728 35.233 6.36 ;
     RECT  35.233 0.576 35.245 6.36 ;
     RECT  35.245 0.576 35.315 5.016 ;
     RECT  35.104 12.528 35.425 13.08 ;
     RECT  35.425 13.008 35.705 13.08 ;
     RECT  35.315 3.072 35.741 5.016 ;
     RECT  35.315 0.576 35.809 1.752 ;
     RECT  35.809 0.144 35.939 1.752 ;
     RECT  35.893 14.928 36.085 14.952 ;
     RECT  35.741 3.072 36.101 3.96 ;
     RECT  35.939 0.144 36.131 0.168 ;
     RECT  35.245 6.24 36.173 6.36 ;
     RECT  36.385 10.752 36.497 10.776 ;
     RECT  35.939 1.68 36.563 1.752 ;
     RECT  36.085 14.832 36.709 14.952 ;
     RECT  36.563 1.728 36.754 1.752 ;
     RECT  36.673 10.8 36.785 10.824 ;
     RECT  36.754 1.728 36.947 1.8 ;
     RECT  36.101 3.072 37.321 3.432 ;
     RECT  35.741 4.992 37.321 5.016 ;
     RECT  36.173 6.24 37.321 6.264 ;
     RECT  37.321 3.072 37.361 6.264 ;
     RECT  35.705 13.056 37.613 13.08 ;
     RECT  37.969 10.8 38.081 10.824 ;
     RECT  36.947 1.728 38.293 1.752 ;
     RECT  37.361 3.072 38.293 5.544 ;
     RECT  38.149 12.528 38.581 12.552 ;
     RECT  36.709 14.208 38.585 14.952 ;
     RECT  38.581 12.528 38.729 12.936 ;
     RECT  38.293 1.728 38.761 5.544 ;
     RECT  38.729 12.912 38.765 12.936 ;
     RECT  38.761 1.728 38.845 5.736 ;
     RECT  38.845 1.728 39.203 5.544 ;
     RECT  38.965 13.008 39.397 13.08 ;
     RECT  39.203 1.728 39.877 1.752 ;
     RECT  39.877 1.104 39.985 1.752 ;
     RECT  39.203 2.88 40.049 5.544 ;
     RECT  39.985 0.576 40.067 1.752 ;
     RECT  39.397 13.008 40.069 13.656 ;
     RECT  40.067 0.576 40.163 0.6 ;
     RECT  40.067 1.68 40.208 1.752 ;
     RECT  40.049 2.88 40.208 6.456 ;
     RECT  40.069 12.24 40.208 13.656 ;
     RECT  38.585 14.928 40.457 14.952 ;
     RECT  40.208 1.68 40.504 13.656 ;
     RECT  40.504 2.88 40.673 5.736 ;
     RECT  40.504 1.68 40.717 1.8 ;
     RECT  40.717 1.68 41.075 1.752 ;
     RECT  40.504 12.528 41.075 13.656 ;
     RECT  40.673 4.464 41.249 5.736 ;
     RECT  41.075 13.056 41.465 13.656 ;
     RECT  41.641 0.576 41.725 0.6 ;
     RECT  40.673 2.88 41.749 3.432 ;
     RECT  41.641 14.208 41.845 14.232 ;
     RECT  41.075 1.728 42.037 1.752 ;
     RECT  41.749 2.784 42.037 3.432 ;
     RECT  41.465 13.056 42.185 13.08 ;
     RECT  42.037 1.728 42.323 3.432 ;
     RECT  42.865 0.576 42.949 0.6 ;
     RECT  42.323 2.784 43.261 3.432 ;
     RECT  41.249 4.512 43.261 5.736 ;
     RECT  42.661 12.528 43.261 12.552 ;
     RECT  43.261 2.784 43.333 5.736 ;
     RECT  43.261 12.528 43.345 13.08 ;
     RECT  42.323 1.728 43.484 1.752 ;
     RECT  43.333 2.784 43.484 5.784 ;
     RECT  43.484 1.728 43.589 5.784 ;
     RECT  43.285 0.144 43.769 0.168 ;
     RECT  43.589 1.728 43.955 5.592 ;
     RECT  43.955 2.784 44.273 5.592 ;
     RECT  43.345 12.528 44.273 12.552 ;
     RECT  41.845 14.208 44.605 14.952 ;
     RECT  44.273 3.024 44.773 5.592 ;
     RECT  43.955 1.728 45.097 1.752 ;
     RECT  44.341 13.056 45.116 13.08 ;
     RECT  44.605 14.928 45.433 14.952 ;
     RECT  45.097 1.728 45.608 1.8 ;
     RECT  44.773 3.024 45.608 6.264 ;
     RECT  45.116 13.056 45.608 13.128 ;
     RECT  45.608 1.728 45.904 13.128 ;
     RECT  45.904 6.816 45.965 6.84 ;
     RECT  45.904 2.88 46.019 5.688 ;
     RECT  45.953 14.208 46.036 14.232 ;
     RECT  46.036 14.16 46.069 14.232 ;
     RECT  45.904 12.288 46.153 12.648 ;
     RECT  46.133 0.576 46.217 0.6 ;
     RECT  46.069 13.632 46.477 14.232 ;
     RECT  46.019 5.232 46.505 5.688 ;
     RECT  46.477 13.632 47.029 13.656 ;
     RECT  45.904 1.728 47.18 1.8 ;
     RECT  46.019 2.88 47.18 4.152 ;
     RECT  47.18 1.728 47.185 4.152 ;
     RECT  46.597 14.928 47.549 14.952 ;
     RECT  47.185 1.728 47.621 4.248 ;
     RECT  46.505 5.52 47.717 5.688 ;
     RECT  47.717 5.52 47.801 6.312 ;
     RECT  47.621 1.728 47.891 3.96 ;
     RECT  47.029 13.056 47.917 13.656 ;
     RECT  47.891 2.88 47.981 3.96 ;
     RECT  47.917 13.632 48.005 13.656 ;
     RECT  47.801 5.52 48.337 5.688 ;
     RECT  48.005 13.632 48.661 14.232 ;
     RECT  48.337 5.136 48.805 5.688 ;
     RECT  48.661 13.632 48.953 14.952 ;
     RECT  47.891 1.728 49.052 1.752 ;
     RECT  47.981 2.88 49.052 3.432 ;
     RECT  49.052 1.728 49.525 3.432 ;
     RECT  48.805 4.56 49.525 5.688 ;
     RECT  48.953 14.208 49.745 14.952 ;
     RECT  49.525 1.728 49.853 5.688 ;
     RECT  49.853 2.832 49.957 5.688 ;
     RECT  49.853 1.728 49.997 1.8 ;
     RECT  48.437 0.144 50.147 0.168 ;
     RECT  49.957 2.832 50.389 5.736 ;
     RECT  49.745 14.208 50.617 14.28 ;
     RECT  50.713 0.576 50.797 0.6 ;
     RECT  50.093 13.056 50.857 13.08 ;
     RECT  50.725 14.928 50.861 14.952 ;
     RECT  50.857 13.056 50.963 13.704 ;
     RECT  49.997 1.728 51.008 1.752 ;
     RECT  50.389 2.832 51.008 6.312 ;
     RECT  50.869 7.44 51.008 7.464 ;
     RECT  50.963 13.056 51.008 13.656 ;
     RECT  51.008 1.728 51.304 13.656 ;
     RECT  51.304 12.288 51.653 13.656 ;
     RECT  51.653 12.96 51.833 13.656 ;
     RECT  51.304 1.728 51.932 2.856 ;
     RECT  51.932 1.68 52.019 2.856 ;
     RECT  51.304 3.936 52.369 6.024 ;
     RECT  52.369 3.84 52.405 6.024 ;
     RECT  51.304 7.44 52.451 7.464 ;
     RECT  51.833 13.056 52.556 13.656 ;
     RECT  51.325 0.144 52.643 0.168 ;
     RECT  52.405 3.84 52.841 6.264 ;
     RECT  52.556 13.056 53.173 13.704 ;
     RECT  52.333 14.928 53.173 14.952 ;
     RECT  52.841 3.84 53.201 6.024 ;
     RECT  53.201 3.84 53.315 5.928 ;
     RECT  52.019 1.728 53.377 2.856 ;
     RECT  53.315 3.936 53.417 5.928 ;
     RECT  53.173 13.056 53.561 14.952 ;
     RECT  53.417 4.656 53.633 5.928 ;
     RECT  53.561 14.208 53.813 14.952 ;
     RECT  53.561 13.056 54.101 13.08 ;
     RECT  53.377 1.728 54.209 2.952 ;
     RECT  54.209 1.728 54.275 1.8 ;
     RECT  54.209 2.832 54.461 2.952 ;
     RECT  53.813 14.88 54.461 14.952 ;
     RECT  53.633 4.656 54.529 5.688 ;
     RECT  54.461 14.88 54.853 14.904 ;
     RECT  54.812 0.528 54.899 0.552 ;
     RECT  54.613 12.912 55.045 12.936 ;
     RECT  55.045 12.528 55.181 12.936 ;
     RECT  55.181 12.816 55.283 12.936 ;
     RECT  54.529 4.464 55.429 5.688 ;
     RECT  54.853 14.208 55.477 14.904 ;
     RECT  54.461 2.88 55.537 2.952 ;
     RECT  55.429 3.936 55.537 5.688 ;
     RECT  54.275 1.728 55.669 1.752 ;
     RECT  55.861 0.576 55.945 0.6 ;
     RECT  55.537 2.88 56.053 5.688 ;
     RECT  55.477 14.208 56.117 14.952 ;
     RECT  55.669 1.728 56.252 1.8 ;
     RECT  56.053 2.88 56.252 5.736 ;
     RECT  56.252 1.728 56.408 5.736 ;
     RECT  55.669 13.056 56.408 13.08 ;
     RECT  56.408 1.728 56.704 13.08 ;
     RECT  56.704 12.912 57.011 13.08 ;
     RECT  56.117 14.208 57.109 14.232 ;
     RECT  56.704 1.728 57.233 5.592 ;
     RECT  57.109 14.208 57.413 14.952 ;
     RECT  57.413 14.208 57.485 14.232 ;
     RECT  57.011 12.96 58.117 13.08 ;
     RECT  58.085 0.576 58.169 0.6 ;
     RECT  57.233 1.728 58.169 5.256 ;
     RECT  58.169 1.728 58.313 3.096 ;
     RECT  58.117 12.96 58.549 13.656 ;
     RECT  58.549 12.528 58.637 13.656 ;
     RECT  58.169 4.128 58.691 5.256 ;
     RECT  58.313 1.728 58.709 2.904 ;
     RECT  58.637 12.72 58.741 13.656 ;
     RECT  58.691 4.128 58.889 5.064 ;
     RECT  58.889 4.128 58.925 4.152 ;
     RECT  58.741 12.72 58.997 14.232 ;
     RECT  58.997 12.72 59.033 13.656 ;
     RECT  58.709 1.728 59.249 2.376 ;
     RECT  59.033 12.72 59.321 13.08 ;
     RECT  59.353 0.576 59.437 0.6 ;
     RECT  59.321 13.056 59.861 13.08 ;
     RECT  59.249 2.304 59.897 2.376 ;
     RECT  59.897 2.304 60.185 2.328 ;
     RECT  61.808 2.148 61.912 12.972 ;
     RECT  61.912 2.418 62.104 12.702 ;
    LAYER M5 ;
     RECT  5.424 0.08 59.4 0.611 ;
     RECT  5.424 0.611 59.208 1.763 ;
     RECT  5.616 1.763 8.712 1.811 ;
     RECT  17.568 1.763 21.096 1.811 ;
     RECT  23.136 1.763 27.864 1.811 ;
     RECT  36.912 1.763 36.936 1.811 ;
     RECT  40.2 1.763 40.68 1.811 ;
     RECT  45.36 1.763 47.88 1.811 ;
     RECT  49.104 1.763 54.264 1.811 ;
     RECT  55.68 1.763 58.584 1.811 ;
     RECT  6 1.811 8.112 1.859 ;
     RECT  17.568 1.811 19.848 1.859 ;
     RECT  23.136 1.811 24.312 1.859 ;
     RECT  29.28 1.763 30.984 1.859 ;
     RECT  42.096 1.763 42.312 1.859 ;
     RECT  50.544 1.811 53.64 1.859 ;
     RECT  2.4 2.137 2.52 2.151 ;
     RECT  61.8 2.137 61.92 2.151 ;
     RECT  10.56 1.763 12.024 2.243 ;
     RECT  13.104 1.763 14.664 2.291 ;
     RECT  16.32 1.763 16.536 2.291 ;
     RECT  17.568 1.859 19.08 2.291 ;
     RECT  25.776 1.811 25.8 2.291 ;
     RECT  27.456 1.811 27.48 2.291 ;
     RECT  29.4 1.859 30.984 2.291 ;
     RECT  32.16 1.763 33.048 2.291 ;
     RECT  34.8 1.763 35.304 2.291 ;
     RECT  38.352 1.763 39.192 2.291 ;
     RECT  42.288 1.859 42.312 2.291 ;
     RECT  47.232 1.811 47.88 2.291 ;
     RECT  49.104 1.811 49.128 2.291 ;
     RECT  56.304 1.811 57.96 2.291 ;
     RECT  14.496 2.291 14.664 2.725 ;
     RECT  43.536 1.763 43.944 2.773 ;
     RECT  24 1.859 24.312 2.821 ;
     RECT  42.624 2.773 43.944 2.821 ;
     RECT  50.544 1.859 53.208 2.821 ;
     RECT  10.56 2.243 11.88 2.915 ;
     RECT  42.624 2.821 44.136 3.013 ;
     RECT  45.6 1.811 45.912 3.013 ;
     RECT  10.56 2.915 11.4 3.109 ;
     RECT  13.104 2.291 13.512 3.205 ;
     RECT  40.2 1.811 40.512 3.301 ;
     RECT  47.76 2.291 47.784 3.301 ;
     RECT  38.784 2.291 38.808 3.397 ;
     RECT  47.76 3.301 48.456 3.397 ;
     RECT  10.08 3.109 11.4 3.491 ;
     RECT  34.8 2.291 35.208 3.539 ;
     RECT  26.784 3.397 26.808 3.733 ;
     RECT  49.872 2.821 53.208 3.829 ;
     RECT  42.624 3.013 45.912 3.877 ;
     RECT  49.872 3.829 53.304 4.019 ;
     RECT  49.872 4.019 51.312 4.163 ;
     RECT  23.28 2.821 24.648 4.355 ;
     RECT  13.056 3.205 13.512 4.501 ;
     RECT  14.496 2.725 15.336 4.501 ;
     RECT  29.4 2.291 29.712 4.501 ;
     RECT  56.4 2.291 56.712 4.501 ;
     RECT  32.448 2.291 33.048 4.547 ;
     RECT  56.304 4.501 56.712 4.549 ;
     RECT  10.08 3.491 10.824 4.595 ;
     RECT  42.624 3.877 46.008 4.595 ;
     RECT  13.056 4.501 15.336 4.643 ;
     RECT  52.656 4.019 53.304 4.643 ;
     RECT  13.056 4.643 14.52 4.691 ;
     RECT  43.248 4.595 46.008 4.691 ;
     RECT  53.28 4.643 53.304 4.691 ;
     RECT  38.784 3.397 38.856 4.787 ;
     RECT  42.24 4.645 42.264 4.787 ;
     RECT  10.08 4.595 10.584 5.027 ;
     RECT  18.6 2.291 19.08 5.171 ;
     RECT  26.592 3.733 26.808 5.171 ;
     RECT  33.024 4.547 33.048 5.171 ;
     RECT  43.248 4.691 45.912 5.171 ;
     RECT  47.76 3.397 48.648 5.219 ;
     RECT  29.28 4.501 29.712 5.267 ;
     RECT  58.656 4.501 58.68 5.267 ;
     RECT  0.144 4.405 0.168 5.411 ;
     RECT  34.8 3.539 35.112 5.605 ;
     RECT  10.56 5.027 10.584 5.747 ;
     RECT  13.2 4.691 14.52 5.747 ;
     RECT  21.072 4.117 21.096 5.747 ;
     RECT  24 4.355 24.648 5.747 ;
     RECT  38.784 4.787 38.808 5.747 ;
     RECT  40.2 3.301 40.968 5.747 ;
     RECT  43.248 5.171 43.368 5.747 ;
     RECT  49.968 4.163 51.312 5.747 ;
     RECT  56.064 4.549 56.712 5.747 ;
     RECT  43.344 5.747 43.368 5.795 ;
     RECT  44.784 5.171 45.912 6.275 ;
     RECT  47.76 5.219 47.784 6.323 ;
     RECT  50.544 5.747 51.312 6.323 ;
     RECT  40.2 5.747 40.512 6.421 ;
     RECT  26.592 5.171 26.616 6.563 ;
     RECT  34.8 5.605 35.208 6.659 ;
     RECT  13.2 5.747 13.656 6.899 ;
     RECT  32.88 5.749 32.904 7.475 ;
     RECT  50.88 6.323 51.312 7.475 ;
     RECT  52.416 6.229 52.44 7.475 ;
     RECT  24 5.747 24.312 11.989 ;
     RECT  45.6 6.275 45.912 12.277 ;
     RECT  51 7.475 51.312 12.277 ;
     RECT  7.8 1.859 8.112 12.517 ;
     RECT  13.2 6.899 13.512 12.517 ;
     RECT  16.32 12.277 16.344 12.517 ;
     RECT  21.888 12.181 21.912 12.517 ;
     RECT  29.4 5.267 29.712 12.517 ;
     RECT  34.8 6.659 35.112 12.517 ;
     RECT  40.08 6.421 40.512 12.517 ;
     RECT  45.6 12.277 46.104 12.659 ;
     RECT  58.56 12.517 58.584 12.709 ;
     RECT  55.056 12.517 55.08 12.805 ;
     RECT  26.832 12.517 26.856 12.901 ;
     RECT  38.16 12.517 38.184 12.901 ;
     RECT  55.056 12.805 55.272 12.901 ;
     RECT  56.4 5.747 56.712 12.901 ;
     RECT  24 11.989 24.504 12.949 ;
     RECT  51 12.277 51.576 12.949 ;
     RECT  56.4 12.901 57 12.949 ;
     RECT  58.56 12.709 59.208 12.949 ;
     RECT  2.4 2.151 2.712 12.969 ;
     RECT  61.8 2.151 62.112 12.969 ;
     RECT  2.4 12.969 2.52 12.983 ;
     RECT  18.6 5.171 18.912 12.983 ;
     RECT  61.8 12.969 61.92 12.983 ;
     RECT  13.2 12.517 14.664 12.997 ;
     RECT  34.8 12.517 35.4 12.997 ;
     RECT  38.16 12.901 38.616 12.997 ;
     RECT  40.08 12.517 41.064 12.997 ;
     RECT  6.816 12.517 8.712 13.045 ;
     RECT  13.008 12.997 14.664 13.045 ;
     RECT  16.32 12.517 16.728 13.045 ;
     RECT  20.448 12.757 20.472 13.045 ;
     RECT  21.888 12.517 22.728 13.045 ;
     RECT  23.904 12.949 24.504 13.045 ;
     RECT  26.64 12.901 26.856 13.045 ;
     RECT  29.28 12.517 29.712 13.045 ;
     RECT  34.8 12.997 35.688 13.045 ;
     RECT  38.16 12.997 41.064 13.045 ;
     RECT  42.672 12.517 43.128 13.045 ;
     RECT  44.16 12.517 44.184 13.045 ;
     RECT  45.6 12.659 45.912 13.045 ;
     RECT  51 12.949 51.768 13.045 ;
     RECT  54.624 12.901 55.272 13.045 ;
     RECT  56.4 12.949 59.208 13.045 ;
     RECT  19.056 13.045 25.608 13.525 ;
     RECT  26.64 13.045 30.168 13.525 ;
     RECT  5.616 13.045 5.64 13.621 ;
     RECT  6.624 13.045 9.336 13.621 ;
     RECT  11.376 13.045 17.592 13.621 ;
     RECT  19.056 13.525 30.168 13.621 ;
     RECT  31.152 13.045 31.176 13.621 ;
     RECT  33.024 13.045 36.312 13.621 ;
     RECT  37.344 13.045 45.912 13.621 ;
     RECT  47.04 13.045 47.88 13.621 ;
     RECT  50.112 13.045 53.016 13.621 ;
     RECT  54.048 13.045 59.4 13.621 ;
     RECT  5.616 13.621 9.336 13.669 ;
     RECT  19.056 13.621 31.176 13.669 ;
     RECT  32.4 13.621 36.312 13.669 ;
     RECT  10.944 13.621 17.976 14.149 ;
     RECT  5.616 13.669 9.72 14.197 ;
     RECT  10.752 14.149 17.976 14.197 ;
     RECT  19.056 13.669 36.312 14.197 ;
     RECT  37.344 13.621 48.888 14.197 ;
     RECT  50.112 13.621 59.4 14.197 ;
     RECT  5.424 14.197 59.4 15.024 ;
     RECT  8.712 1.763 10.56 1.811 ;
     RECT  12.024 1.763 13.104 2.243 ;
     RECT  14.664 1.763 16.32 2.291 ;
     RECT  16.536 1.763 17.568 2.291 ;
     RECT  27.864 1.763 29.28 1.811 ;
     RECT  30.984 1.763 32.16 2.291 ;
     RECT  36.936 1.763 38.352 1.811 ;
     RECT  39.192 1.763 40.2 2.291 ;
     RECT  40.68 1.763 42.096 1.811 ;
     RECT  42.312 1.763 43.536 2.291 ;
     RECT  43.944 1.763 45.36 1.811 ;
     RECT  47.88 1.763 49.104 2.291 ;
     RECT  54.264 1.763 55.68 1.811 ;
     RECT  10.08 1.811 10.56 3.109 ;
     RECT  24.312 1.811 25.776 2.291 ;
     RECT  40.512 1.811 42.096 1.859 ;
     RECT  43.944 1.811 45.6 2.821 ;
     RECT  45.912 1.811 47.232 2.291 ;
     RECT  49.128 1.811 50.544 2.291 ;
     RECT  23.28 1.859 24 2.821 ;
     RECT  40.512 1.859 42.288 2.291 ;
     RECT  11.88 2.243 13.104 2.915 ;
     RECT  13.512 2.291 14.496 4.501 ;
     RECT  14.664 2.291 15.336 2.725 ;
     RECT  24.312 2.291 24.648 2.821 ;
     RECT  38.808 2.291 40.2 3.397 ;
     RECT  40.512 2.291 40.968 3.301 ;
     RECT  42.624 2.291 43.536 2.773 ;
     RECT  47.784 2.291 50.544 2.821 ;
     RECT  44.136 2.821 45.6 3.013 ;
     RECT  47.784 2.821 49.872 3.301 ;
     RECT  13.056 2.915 13.104 3.205 ;
     RECT  48.456 3.301 49.872 3.397 ;
     RECT  38.856 3.397 40.2 4.787 ;
     RECT  48.648 3.397 49.872 4.163 ;
     RECT  51.312 4.019 52.656 4.643 ;
     RECT  48.648 4.163 49.968 5.219 ;
     RECT  32.88 4.547 33.024 5.171 ;
     RECT  42.624 4.595 43.248 4.645 ;
     RECT  40.968 4.645 42.24 4.787 ;
     RECT  42.264 4.645 43.248 4.787 ;
     RECT  38.808 4.787 40.2 5.747 ;
     RECT  32.88 5.171 32.904 5.749 ;
     RECT  43.368 5.171 44.784 5.795 ;
     RECT  40.08 5.747 40.2 6.421 ;
     RECT  51.312 6.229 52.416 7.475 ;
     RECT  22.728 12.517 24 12.949 ;
     RECT  43.128 12.517 44.16 13.045 ;
     RECT  44.184 12.517 45.6 13.045 ;
     RECT  55.08 12.517 56.4 12.805 ;
     RECT  45.912 12.659 46.104 13.045 ;
     RECT  20.472 12.757 21.888 13.045 ;
     RECT  55.272 12.805 56.4 13.045 ;
     RECT  38.616 12.901 40.08 12.997 ;
     RECT  22.728 12.949 23.904 13.045 ;
     RECT  18.6 12.983 18.912 13.045 ;
     RECT  5.64 13.045 6.624 13.621 ;
     RECT  17.592 13.045 19.056 13.621 ;
     RECT  25.608 13.045 26.64 13.525 ;
     RECT  30.168 13.045 31.152 13.621 ;
     RECT  36.312 13.045 37.344 14.197 ;
     RECT  45.912 13.045 47.04 13.621 ;
     RECT  53.016 13.045 54.048 13.621 ;
     RECT  17.976 13.621 19.056 14.197 ;
     RECT  31.176 13.621 32.4 13.669 ;
     RECT  48.888 13.621 50.112 14.197 ;
     RECT  9.72 13.669 10.944 14.149 ;
     RECT  9.72 14.149 10.752 14.197 ;
  END
END qkh_packet_h263
END LIBRARY
